VERSION 5.8 ;
BUSBITCHARS "[]" ;
DIVIDERCHAR "/" ;
UNITS
    DATABASE MICRONS 1000 ;
END UNITS

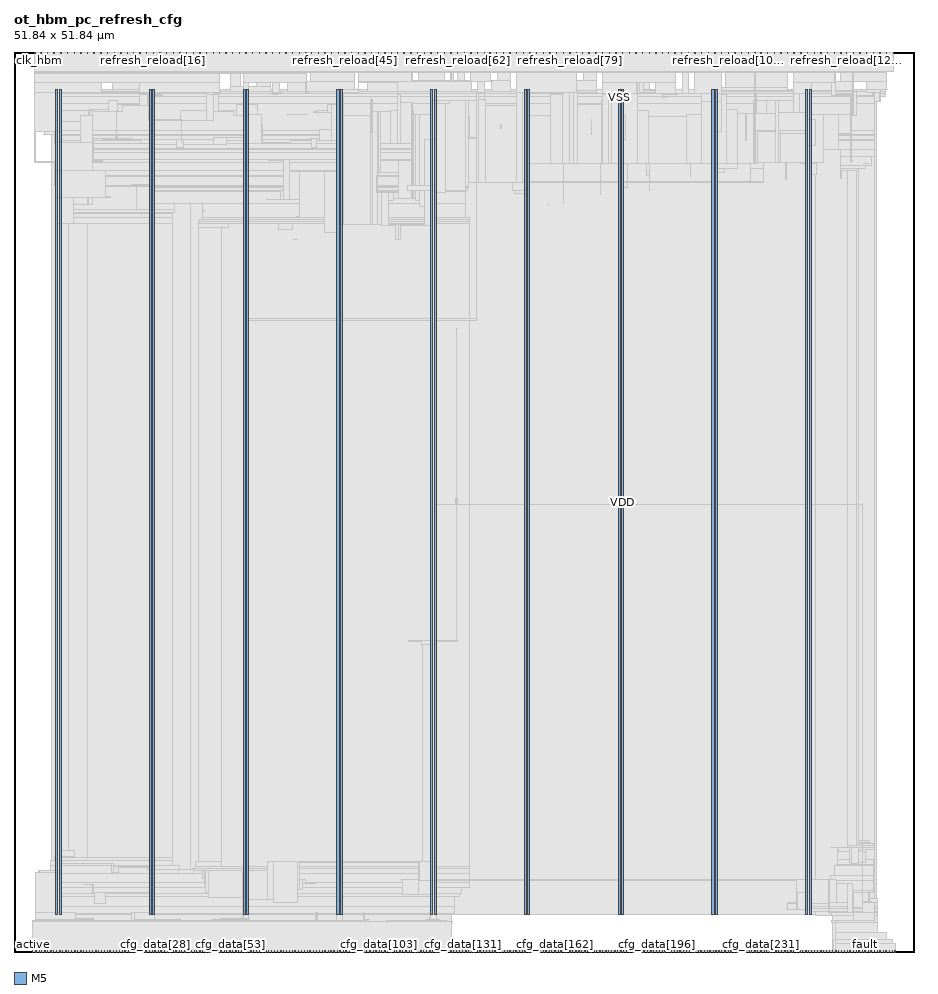
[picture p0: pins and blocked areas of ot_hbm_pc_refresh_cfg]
MACRO ot_hbm_pc_refresh_cfg
  FOREIGN ot_hbm_pc_refresh_cfg 0 0 ;
  CLASS BLOCK ;
  SIZE 51.84 BY 51.84 ;
  PIN active
    DIRECTION OUTPUT ;
    USE SIGNAL ;
    PORT
      LAYER M5 ;
        RECT  1.056 0 1.08 0.084 ;
    END
  END active
  PIN cfg_addr[0]
    DIRECTION INPUT ;
    USE SIGNAL ;
    PORT
      LAYER M5 ;
        RECT  1.248 0 1.272 0.084 ;
    END
  END cfg_addr[0]
  PIN cfg_addr[10]
    DIRECTION INPUT ;
    USE SIGNAL ;
    PORT
      LAYER M5 ;
        RECT  2.976 0 3 0.084 ;
    END
  END cfg_addr[10]
  PIN cfg_addr[11]
    DIRECTION INPUT ;
    USE SIGNAL ;
    PORT
      LAYER M5 ;
        RECT  3.12 0 3.144 0.084 ;
    END
  END cfg_addr[11]
  PIN cfg_addr[1]
    DIRECTION INPUT ;
    USE SIGNAL ;
    PORT
      LAYER M5 ;
        RECT  1.44 0 1.464 0.084 ;
    END
  END cfg_addr[1]
  PIN cfg_addr[2]
    DIRECTION INPUT ;
    USE SIGNAL ;
    PORT
      LAYER M5 ;
        RECT  1.584 0 1.608 0.084 ;
    END
  END cfg_addr[2]
  PIN cfg_addr[3]
    DIRECTION INPUT ;
    USE SIGNAL ;
    PORT
      LAYER M5 ;
        RECT  1.776 0 1.8 0.084 ;
    END
  END cfg_addr[3]
  PIN cfg_addr[4]
    DIRECTION INPUT ;
    USE SIGNAL ;
    PORT
      LAYER M5 ;
        RECT  1.92 0 1.944 0.084 ;
    END
  END cfg_addr[4]
  PIN cfg_addr[5]
    DIRECTION INPUT ;
    USE SIGNAL ;
    PORT
      LAYER M5 ;
        RECT  2.112 0 2.136 0.084 ;
    END
  END cfg_addr[5]
  PIN cfg_addr[6]
    DIRECTION INPUT ;
    USE SIGNAL ;
    PORT
      LAYER M5 ;
        RECT  2.256 0 2.28 0.084 ;
    END
  END cfg_addr[6]
  PIN cfg_addr[7]
    DIRECTION INPUT ;
    USE SIGNAL ;
    PORT
      LAYER M5 ;
        RECT  2.448 0 2.472 0.084 ;
    END
  END cfg_addr[7]
  PIN cfg_addr[8]
    DIRECTION INPUT ;
    USE SIGNAL ;
    PORT
      LAYER M5 ;
        RECT  2.64 0 2.664 0.084 ;
    END
  END cfg_addr[8]
  PIN cfg_addr[9]
    DIRECTION INPUT ;
    USE SIGNAL ;
    PORT
      LAYER M5 ;
        RECT  2.784 0 2.808 0.084 ;
    END
  END cfg_addr[9]
  PIN cfg_data[0]
    DIRECTION INPUT ;
    USE SIGNAL ;
    PORT
      LAYER M5 ;
        RECT  3.312 0 3.336 0.084 ;
    END
  END cfg_data[0]
  PIN cfg_data[100]
    DIRECTION INPUT ;
    USE SIGNAL ;
    PORT
      LAYER M5 ;
        RECT  20.496 0 20.52 0.084 ;
    END
  END cfg_data[100]
  PIN cfg_data[101]
    DIRECTION INPUT ;
    USE SIGNAL ;
    PORT
      LAYER M5 ;
        RECT  20.688 0 20.712 0.084 ;
    END
  END cfg_data[101]
  PIN cfg_data[102]
    DIRECTION INPUT ;
    USE SIGNAL ;
    PORT
      LAYER M5 ;
        RECT  20.832 0 20.856 0.084 ;
    END
  END cfg_data[102]
  PIN cfg_data[103]
    DIRECTION INPUT ;
    USE SIGNAL ;
    PORT
      LAYER M5 ;
        RECT  21.024 0 21.048 0.084 ;
    END
  END cfg_data[103]
  PIN cfg_data[104]
    DIRECTION INPUT ;
    USE SIGNAL ;
    PORT
      LAYER M5 ;
        RECT  21.168 0 21.192 0.084 ;
    END
  END cfg_data[104]
  PIN cfg_data[105]
    DIRECTION INPUT ;
    USE SIGNAL ;
    PORT
      LAYER M5 ;
        RECT  21.36 0 21.384 0.084 ;
    END
  END cfg_data[105]
  PIN cfg_data[106]
    DIRECTION INPUT ;
    USE SIGNAL ;
    PORT
      LAYER M5 ;
        RECT  21.504 0 21.528 0.084 ;
    END
  END cfg_data[106]
  PIN cfg_data[107]
    DIRECTION INPUT ;
    USE SIGNAL ;
    PORT
      LAYER M5 ;
        RECT  21.696 0 21.72 0.084 ;
    END
  END cfg_data[107]
  PIN cfg_data[108]
    DIRECTION INPUT ;
    USE SIGNAL ;
    PORT
      LAYER M5 ;
        RECT  21.888 0 21.912 0.084 ;
    END
  END cfg_data[108]
  PIN cfg_data[109]
    DIRECTION INPUT ;
    USE SIGNAL ;
    PORT
      LAYER M5 ;
        RECT  22.032 0 22.056 0.084 ;
    END
  END cfg_data[109]
  PIN cfg_data[10]
    DIRECTION INPUT ;
    USE SIGNAL ;
    PORT
      LAYER M5 ;
        RECT  5.04 0 5.064 0.084 ;
    END
  END cfg_data[10]
  PIN cfg_data[110]
    DIRECTION INPUT ;
    USE SIGNAL ;
    PORT
      LAYER M5 ;
        RECT  22.224 0 22.248 0.084 ;
    END
  END cfg_data[110]
  PIN cfg_data[111]
    DIRECTION INPUT ;
    USE SIGNAL ;
    PORT
      LAYER M5 ;
        RECT  22.368 0 22.392 0.084 ;
    END
  END cfg_data[111]
  PIN cfg_data[112]
    DIRECTION INPUT ;
    USE SIGNAL ;
    PORT
      LAYER M5 ;
        RECT  22.56 0 22.584 0.084 ;
    END
  END cfg_data[112]
  PIN cfg_data[113]
    DIRECTION INPUT ;
    USE SIGNAL ;
    PORT
      LAYER M5 ;
        RECT  22.752 0 22.776 0.084 ;
    END
  END cfg_data[113]
  PIN cfg_data[114]
    DIRECTION INPUT ;
    USE SIGNAL ;
    PORT
      LAYER M5 ;
        RECT  22.896 0 22.92 0.084 ;
    END
  END cfg_data[114]
  PIN cfg_data[115]
    DIRECTION INPUT ;
    USE SIGNAL ;
    PORT
      LAYER M5 ;
        RECT  23.088 0 23.112 0.084 ;
    END
  END cfg_data[115]
  PIN cfg_data[116]
    DIRECTION INPUT ;
    USE SIGNAL ;
    PORT
      LAYER M5 ;
        RECT  23.232 0 23.256 0.084 ;
    END
  END cfg_data[116]
  PIN cfg_data[117]
    DIRECTION INPUT ;
    USE SIGNAL ;
    PORT
      LAYER M5 ;
        RECT  23.424 0 23.448 0.084 ;
    END
  END cfg_data[117]
  PIN cfg_data[118]
    DIRECTION INPUT ;
    USE SIGNAL ;
    PORT
      LAYER M5 ;
        RECT  23.568 0 23.592 0.084 ;
    END
  END cfg_data[118]
  PIN cfg_data[119]
    DIRECTION INPUT ;
    USE SIGNAL ;
    PORT
      LAYER M5 ;
        RECT  23.76 0 23.784 0.084 ;
    END
  END cfg_data[119]
  PIN cfg_data[11]
    DIRECTION INPUT ;
    USE SIGNAL ;
    PORT
      LAYER M5 ;
        RECT  5.184 0 5.208 0.084 ;
    END
  END cfg_data[11]
  PIN cfg_data[120]
    DIRECTION INPUT ;
    USE SIGNAL ;
    PORT
      LAYER M5 ;
        RECT  23.952 0 23.976 0.084 ;
    END
  END cfg_data[120]
  PIN cfg_data[121]
    DIRECTION INPUT ;
    USE SIGNAL ;
    PORT
      LAYER M5 ;
        RECT  24.096 0 24.12 0.084 ;
    END
  END cfg_data[121]
  PIN cfg_data[122]
    DIRECTION INPUT ;
    USE SIGNAL ;
    PORT
      LAYER M5 ;
        RECT  24.288 0 24.312 0.084 ;
    END
  END cfg_data[122]
  PIN cfg_data[123]
    DIRECTION INPUT ;
    USE SIGNAL ;
    PORT
      LAYER M5 ;
        RECT  24.432 0 24.456 0.084 ;
    END
  END cfg_data[123]
  PIN cfg_data[124]
    DIRECTION INPUT ;
    USE SIGNAL ;
    PORT
      LAYER M5 ;
        RECT  24.624 0 24.648 0.084 ;
    END
  END cfg_data[124]
  PIN cfg_data[125]
    DIRECTION INPUT ;
    USE SIGNAL ;
    PORT
      LAYER M5 ;
        RECT  24.768 0 24.792 0.084 ;
    END
  END cfg_data[125]
  PIN cfg_data[126]
    DIRECTION INPUT ;
    USE SIGNAL ;
    PORT
      LAYER M5 ;
        RECT  24.96 0 24.984 0.084 ;
    END
  END cfg_data[126]
  PIN cfg_data[127]
    DIRECTION INPUT ;
    USE SIGNAL ;
    PORT
      LAYER M5 ;
        RECT  25.152 0 25.176 0.084 ;
    END
  END cfg_data[127]
  PIN cfg_data[128]
    DIRECTION INPUT ;
    USE SIGNAL ;
    PORT
      LAYER M5 ;
        RECT  25.296 0 25.32 0.084 ;
    END
  END cfg_data[128]
  PIN cfg_data[129]
    DIRECTION INPUT ;
    USE SIGNAL ;
    PORT
      LAYER M5 ;
        RECT  25.488 0 25.512 0.084 ;
    END
  END cfg_data[129]
  PIN cfg_data[12]
    DIRECTION INPUT ;
    USE SIGNAL ;
    PORT
      LAYER M5 ;
        RECT  5.376 0 5.4 0.084 ;
    END
  END cfg_data[12]
  PIN cfg_data[130]
    DIRECTION INPUT ;
    USE SIGNAL ;
    PORT
      LAYER M5 ;
        RECT  25.632 0 25.656 0.084 ;
    END
  END cfg_data[130]
  PIN cfg_data[131]
    DIRECTION INPUT ;
    USE SIGNAL ;
    PORT
      LAYER M5 ;
        RECT  25.824 0 25.848 0.084 ;
    END
  END cfg_data[131]
  PIN cfg_data[132]
    DIRECTION INPUT ;
    USE SIGNAL ;
    PORT
      LAYER M5 ;
        RECT  26.016 0 26.04 0.084 ;
    END
  END cfg_data[132]
  PIN cfg_data[133]
    DIRECTION INPUT ;
    USE SIGNAL ;
    PORT
      LAYER M5 ;
        RECT  26.16 0 26.184 0.084 ;
    END
  END cfg_data[133]
  PIN cfg_data[134]
    DIRECTION INPUT ;
    USE SIGNAL ;
    PORT
      LAYER M5 ;
        RECT  26.352 0 26.376 0.084 ;
    END
  END cfg_data[134]
  PIN cfg_data[135]
    DIRECTION INPUT ;
    USE SIGNAL ;
    PORT
      LAYER M5 ;
        RECT  26.496 0 26.52 0.084 ;
    END
  END cfg_data[135]
  PIN cfg_data[136]
    DIRECTION INPUT ;
    USE SIGNAL ;
    PORT
      LAYER M5 ;
        RECT  26.688 0 26.712 0.084 ;
    END
  END cfg_data[136]
  PIN cfg_data[137]
    DIRECTION INPUT ;
    USE SIGNAL ;
    PORT
      LAYER M5 ;
        RECT  26.832 0 26.856 0.084 ;
    END
  END cfg_data[137]
  PIN cfg_data[138]
    DIRECTION INPUT ;
    USE SIGNAL ;
    PORT
      LAYER M5 ;
        RECT  27.024 0 27.048 0.084 ;
    END
  END cfg_data[138]
  PIN cfg_data[139]
    DIRECTION INPUT ;
    USE SIGNAL ;
    PORT
      LAYER M5 ;
        RECT  27.216 0 27.24 0.084 ;
    END
  END cfg_data[139]
  PIN cfg_data[13]
    DIRECTION INPUT ;
    USE SIGNAL ;
    PORT
      LAYER M5 ;
        RECT  5.52 0 5.544 0.084 ;
    END
  END cfg_data[13]
  PIN cfg_data[140]
    DIRECTION INPUT ;
    USE SIGNAL ;
    PORT
      LAYER M5 ;
        RECT  27.36 0 27.384 0.084 ;
    END
  END cfg_data[140]
  PIN cfg_data[141]
    DIRECTION INPUT ;
    USE SIGNAL ;
    PORT
      LAYER M5 ;
        RECT  27.552 0 27.576 0.084 ;
    END
  END cfg_data[141]
  PIN cfg_data[142]
    DIRECTION INPUT ;
    USE SIGNAL ;
    PORT
      LAYER M5 ;
        RECT  27.696 0 27.72 0.084 ;
    END
  END cfg_data[142]
  PIN cfg_data[143]
    DIRECTION INPUT ;
    USE SIGNAL ;
    PORT
      LAYER M5 ;
        RECT  27.888 0 27.912 0.084 ;
    END
  END cfg_data[143]
  PIN cfg_data[144]
    DIRECTION INPUT ;
    USE SIGNAL ;
    PORT
      LAYER M5 ;
        RECT  28.08 0 28.104 0.084 ;
    END
  END cfg_data[144]
  PIN cfg_data[145]
    DIRECTION INPUT ;
    USE SIGNAL ;
    PORT
      LAYER M5 ;
        RECT  28.224 0 28.248 0.084 ;
    END
  END cfg_data[145]
  PIN cfg_data[146]
    DIRECTION INPUT ;
    USE SIGNAL ;
    PORT
      LAYER M5 ;
        RECT  28.416 0 28.44 0.084 ;
    END
  END cfg_data[146]
  PIN cfg_data[147]
    DIRECTION INPUT ;
    USE SIGNAL ;
    PORT
      LAYER M5 ;
        RECT  28.56 0 28.584 0.084 ;
    END
  END cfg_data[147]
  PIN cfg_data[148]
    DIRECTION INPUT ;
    USE SIGNAL ;
    PORT
      LAYER M5 ;
        RECT  28.752 0 28.776 0.084 ;
    END
  END cfg_data[148]
  PIN cfg_data[149]
    DIRECTION INPUT ;
    USE SIGNAL ;
    PORT
      LAYER M5 ;
        RECT  28.896 0 28.92 0.084 ;
    END
  END cfg_data[149]
  PIN cfg_data[14]
    DIRECTION INPUT ;
    USE SIGNAL ;
    PORT
      LAYER M5 ;
        RECT  5.712 0 5.736 0.084 ;
    END
  END cfg_data[14]
  PIN cfg_data[150]
    DIRECTION INPUT ;
    USE SIGNAL ;
    PORT
      LAYER M5 ;
        RECT  29.088 0 29.112 0.084 ;
    END
  END cfg_data[150]
  PIN cfg_data[151]
    DIRECTION INPUT ;
    USE SIGNAL ;
    PORT
      LAYER M5 ;
        RECT  29.28 0 29.304 0.084 ;
    END
  END cfg_data[151]
  PIN cfg_data[152]
    DIRECTION INPUT ;
    USE SIGNAL ;
    PORT
      LAYER M5 ;
        RECT  29.424 0 29.448 0.084 ;
    END
  END cfg_data[152]
  PIN cfg_data[153]
    DIRECTION INPUT ;
    USE SIGNAL ;
    PORT
      LAYER M5 ;
        RECT  29.616 0 29.64 0.084 ;
    END
  END cfg_data[153]
  PIN cfg_data[154]
    DIRECTION INPUT ;
    USE SIGNAL ;
    PORT
      LAYER M5 ;
        RECT  29.76 0 29.784 0.084 ;
    END
  END cfg_data[154]
  PIN cfg_data[155]
    DIRECTION INPUT ;
    USE SIGNAL ;
    PORT
      LAYER M5 ;
        RECT  29.952 0 29.976 0.084 ;
    END
  END cfg_data[155]
  PIN cfg_data[156]
    DIRECTION INPUT ;
    USE SIGNAL ;
    PORT
      LAYER M5 ;
        RECT  30.096 0 30.12 0.084 ;
    END
  END cfg_data[156]
  PIN cfg_data[157]
    DIRECTION INPUT ;
    USE SIGNAL ;
    PORT
      LAYER M5 ;
        RECT  30.288 0 30.312 0.084 ;
    END
  END cfg_data[157]
  PIN cfg_data[158]
    DIRECTION INPUT ;
    USE SIGNAL ;
    PORT
      LAYER M5 ;
        RECT  30.48 0 30.504 0.084 ;
    END
  END cfg_data[158]
  PIN cfg_data[159]
    DIRECTION INPUT ;
    USE SIGNAL ;
    PORT
      LAYER M5 ;
        RECT  30.624 0 30.648 0.084 ;
    END
  END cfg_data[159]
  PIN cfg_data[15]
    DIRECTION INPUT ;
    USE SIGNAL ;
    PORT
      LAYER M5 ;
        RECT  5.904 0 5.928 0.084 ;
    END
  END cfg_data[15]
  PIN cfg_data[160]
    DIRECTION INPUT ;
    USE SIGNAL ;
    PORT
      LAYER M5 ;
        RECT  30.816 0 30.84 0.084 ;
    END
  END cfg_data[160]
  PIN cfg_data[161]
    DIRECTION INPUT ;
    USE SIGNAL ;
    PORT
      LAYER M5 ;
        RECT  30.96 0 30.984 0.084 ;
    END
  END cfg_data[161]
  PIN cfg_data[162]
    DIRECTION INPUT ;
    USE SIGNAL ;
    PORT
      LAYER M5 ;
        RECT  31.152 0 31.176 0.084 ;
    END
  END cfg_data[162]
  PIN cfg_data[163]
    DIRECTION INPUT ;
    USE SIGNAL ;
    PORT
      LAYER M5 ;
        RECT  31.344 0 31.368 0.084 ;
    END
  END cfg_data[163]
  PIN cfg_data[164]
    DIRECTION INPUT ;
    USE SIGNAL ;
    PORT
      LAYER M5 ;
        RECT  31.488 0 31.512 0.084 ;
    END
  END cfg_data[164]
  PIN cfg_data[165]
    DIRECTION INPUT ;
    USE SIGNAL ;
    PORT
      LAYER M5 ;
        RECT  31.68 0 31.704 0.084 ;
    END
  END cfg_data[165]
  PIN cfg_data[166]
    DIRECTION INPUT ;
    USE SIGNAL ;
    PORT
      LAYER M5 ;
        RECT  31.824 0 31.848 0.084 ;
    END
  END cfg_data[166]
  PIN cfg_data[167]
    DIRECTION INPUT ;
    USE SIGNAL ;
    PORT
      LAYER M5 ;
        RECT  32.016 0 32.04 0.084 ;
    END
  END cfg_data[167]
  PIN cfg_data[168]
    DIRECTION INPUT ;
    USE SIGNAL ;
    PORT
      LAYER M5 ;
        RECT  32.16 0 32.184 0.084 ;
    END
  END cfg_data[168]
  PIN cfg_data[169]
    DIRECTION INPUT ;
    USE SIGNAL ;
    PORT
      LAYER M5 ;
        RECT  32.352 0 32.376 0.084 ;
    END
  END cfg_data[169]
  PIN cfg_data[16]
    DIRECTION INPUT ;
    USE SIGNAL ;
    PORT
      LAYER M5 ;
        RECT  6.048 0 6.072 0.084 ;
    END
  END cfg_data[16]
  PIN cfg_data[170]
    DIRECTION INPUT ;
    USE SIGNAL ;
    PORT
      LAYER M5 ;
        RECT  32.544 0 32.568 0.084 ;
    END
  END cfg_data[170]
  PIN cfg_data[171]
    DIRECTION INPUT ;
    USE SIGNAL ;
    PORT
      LAYER M5 ;
        RECT  32.688 0 32.712 0.084 ;
    END
  END cfg_data[171]
  PIN cfg_data[172]
    DIRECTION INPUT ;
    USE SIGNAL ;
    PORT
      LAYER M5 ;
        RECT  32.88 0 32.904 0.084 ;
    END
  END cfg_data[172]
  PIN cfg_data[173]
    DIRECTION INPUT ;
    USE SIGNAL ;
    PORT
      LAYER M5 ;
        RECT  33.024 0 33.048 0.084 ;
    END
  END cfg_data[173]
  PIN cfg_data[174]
    DIRECTION INPUT ;
    USE SIGNAL ;
    PORT
      LAYER M5 ;
        RECT  33.216 0 33.24 0.084 ;
    END
  END cfg_data[174]
  PIN cfg_data[175]
    DIRECTION INPUT ;
    USE SIGNAL ;
    PORT
      LAYER M5 ;
        RECT  33.408 0 33.432 0.084 ;
    END
  END cfg_data[175]
  PIN cfg_data[176]
    DIRECTION INPUT ;
    USE SIGNAL ;
    PORT
      LAYER M5 ;
        RECT  33.552 0 33.576 0.084 ;
    END
  END cfg_data[176]
  PIN cfg_data[177]
    DIRECTION INPUT ;
    USE SIGNAL ;
    PORT
      LAYER M5 ;
        RECT  33.744 0 33.768 0.084 ;
    END
  END cfg_data[177]
  PIN cfg_data[178]
    DIRECTION INPUT ;
    USE SIGNAL ;
    PORT
      LAYER M5 ;
        RECT  33.888 0 33.912 0.084 ;
    END
  END cfg_data[178]
  PIN cfg_data[179]
    DIRECTION INPUT ;
    USE SIGNAL ;
    PORT
      LAYER M5 ;
        RECT  34.08 0 34.104 0.084 ;
    END
  END cfg_data[179]
  PIN cfg_data[17]
    DIRECTION INPUT ;
    USE SIGNAL ;
    PORT
      LAYER M5 ;
        RECT  6.24 0 6.264 0.084 ;
    END
  END cfg_data[17]
  PIN cfg_data[180]
    DIRECTION INPUT ;
    USE SIGNAL ;
    PORT
      LAYER M5 ;
        RECT  34.224 0 34.248 0.084 ;
    END
  END cfg_data[180]
  PIN cfg_data[181]
    DIRECTION INPUT ;
    USE SIGNAL ;
    PORT
      LAYER M5 ;
        RECT  34.416 0 34.44 0.084 ;
    END
  END cfg_data[181]
  PIN cfg_data[182]
    DIRECTION INPUT ;
    USE SIGNAL ;
    PORT
      LAYER M5 ;
        RECT  34.608 0 34.632 0.084 ;
    END
  END cfg_data[182]
  PIN cfg_data[183]
    DIRECTION INPUT ;
    USE SIGNAL ;
    PORT
      LAYER M5 ;
        RECT  34.752 0 34.776 0.084 ;
    END
  END cfg_data[183]
  PIN cfg_data[184]
    DIRECTION INPUT ;
    USE SIGNAL ;
    PORT
      LAYER M5 ;
        RECT  34.944 0 34.968 0.084 ;
    END
  END cfg_data[184]
  PIN cfg_data[185]
    DIRECTION INPUT ;
    USE SIGNAL ;
    PORT
      LAYER M5 ;
        RECT  35.088 0 35.112 0.084 ;
    END
  END cfg_data[185]
  PIN cfg_data[186]
    DIRECTION INPUT ;
    USE SIGNAL ;
    PORT
      LAYER M5 ;
        RECT  35.28 0 35.304 0.084 ;
    END
  END cfg_data[186]
  PIN cfg_data[187]
    DIRECTION INPUT ;
    USE SIGNAL ;
    PORT
      LAYER M5 ;
        RECT  35.424 0 35.448 0.084 ;
    END
  END cfg_data[187]
  PIN cfg_data[188]
    DIRECTION INPUT ;
    USE SIGNAL ;
    PORT
      LAYER M5 ;
        RECT  35.616 0 35.64 0.084 ;
    END
  END cfg_data[188]
  PIN cfg_data[189]
    DIRECTION INPUT ;
    USE SIGNAL ;
    PORT
      LAYER M5 ;
        RECT  35.808 0 35.832 0.084 ;
    END
  END cfg_data[189]
  PIN cfg_data[18]
    DIRECTION INPUT ;
    USE SIGNAL ;
    PORT
      LAYER M5 ;
        RECT  6.384 0 6.408 0.084 ;
    END
  END cfg_data[18]
  PIN cfg_data[190]
    DIRECTION INPUT ;
    USE SIGNAL ;
    PORT
      LAYER M5 ;
        RECT  35.952 0 35.976 0.084 ;
    END
  END cfg_data[190]
  PIN cfg_data[191]
    DIRECTION INPUT ;
    USE SIGNAL ;
    PORT
      LAYER M5 ;
        RECT  36.144 0 36.168 0.084 ;
    END
  END cfg_data[191]
  PIN cfg_data[192]
    DIRECTION INPUT ;
    USE SIGNAL ;
    PORT
      LAYER M5 ;
        RECT  36.288 0 36.312 0.084 ;
    END
  END cfg_data[192]
  PIN cfg_data[193]
    DIRECTION INPUT ;
    USE SIGNAL ;
    PORT
      LAYER M5 ;
        RECT  36.48 0 36.504 0.084 ;
    END
  END cfg_data[193]
  PIN cfg_data[194]
    DIRECTION INPUT ;
    USE SIGNAL ;
    PORT
      LAYER M5 ;
        RECT  36.672 0 36.696 0.084 ;
    END
  END cfg_data[194]
  PIN cfg_data[195]
    DIRECTION INPUT ;
    USE SIGNAL ;
    PORT
      LAYER M5 ;
        RECT  36.816 0 36.84 0.084 ;
    END
  END cfg_data[195]
  PIN cfg_data[196]
    DIRECTION INPUT ;
    USE SIGNAL ;
    PORT
      LAYER M5 ;
        RECT  37.008 0 37.032 0.084 ;
    END
  END cfg_data[196]
  PIN cfg_data[197]
    DIRECTION INPUT ;
    USE SIGNAL ;
    PORT
      LAYER M5 ;
        RECT  37.152 0 37.176 0.084 ;
    END
  END cfg_data[197]
  PIN cfg_data[198]
    DIRECTION INPUT ;
    USE SIGNAL ;
    PORT
      LAYER M5 ;
        RECT  37.344 0 37.368 0.084 ;
    END
  END cfg_data[198]
  PIN cfg_data[199]
    DIRECTION INPUT ;
    USE SIGNAL ;
    PORT
      LAYER M5 ;
        RECT  37.488 0 37.512 0.084 ;
    END
  END cfg_data[199]
  PIN cfg_data[19]
    DIRECTION INPUT ;
    USE SIGNAL ;
    PORT
      LAYER M5 ;
        RECT  6.576 0 6.6 0.084 ;
    END
  END cfg_data[19]
  PIN cfg_data[1]
    DIRECTION INPUT ;
    USE SIGNAL ;
    PORT
      LAYER M5 ;
        RECT  3.504 0 3.528 0.084 ;
    END
  END cfg_data[1]
  PIN cfg_data[200]
    DIRECTION INPUT ;
    USE SIGNAL ;
    PORT
      LAYER M5 ;
        RECT  37.68 0 37.704 0.084 ;
    END
  END cfg_data[200]
  PIN cfg_data[201]
    DIRECTION INPUT ;
    USE SIGNAL ;
    PORT
      LAYER M5 ;
        RECT  37.872 0 37.896 0.084 ;
    END
  END cfg_data[201]
  PIN cfg_data[202]
    DIRECTION INPUT ;
    USE SIGNAL ;
    PORT
      LAYER M5 ;
        RECT  38.016 0 38.04 0.084 ;
    END
  END cfg_data[202]
  PIN cfg_data[203]
    DIRECTION INPUT ;
    USE SIGNAL ;
    PORT
      LAYER M5 ;
        RECT  38.208 0 38.232 0.084 ;
    END
  END cfg_data[203]
  PIN cfg_data[204]
    DIRECTION INPUT ;
    USE SIGNAL ;
    PORT
      LAYER M5 ;
        RECT  38.352 0 38.376 0.084 ;
    END
  END cfg_data[204]
  PIN cfg_data[205]
    DIRECTION INPUT ;
    USE SIGNAL ;
    PORT
      LAYER M5 ;
        RECT  38.544 0 38.568 0.084 ;
    END
  END cfg_data[205]
  PIN cfg_data[206]
    DIRECTION INPUT ;
    USE SIGNAL ;
    PORT
      LAYER M5 ;
        RECT  38.736 0 38.76 0.084 ;
    END
  END cfg_data[206]
  PIN cfg_data[207]
    DIRECTION INPUT ;
    USE SIGNAL ;
    PORT
      LAYER M5 ;
        RECT  38.88 0 38.904 0.084 ;
    END
  END cfg_data[207]
  PIN cfg_data[208]
    DIRECTION INPUT ;
    USE SIGNAL ;
    PORT
      LAYER M5 ;
        RECT  39.072 0 39.096 0.084 ;
    END
  END cfg_data[208]
  PIN cfg_data[209]
    DIRECTION INPUT ;
    USE SIGNAL ;
    PORT
      LAYER M5 ;
        RECT  39.216 0 39.24 0.084 ;
    END
  END cfg_data[209]
  PIN cfg_data[20]
    DIRECTION INPUT ;
    USE SIGNAL ;
    PORT
      LAYER M5 ;
        RECT  6.768 0 6.792 0.084 ;
    END
  END cfg_data[20]
  PIN cfg_data[210]
    DIRECTION INPUT ;
    USE SIGNAL ;
    PORT
      LAYER M5 ;
        RECT  39.408 0 39.432 0.084 ;
    END
  END cfg_data[210]
  PIN cfg_data[211]
    DIRECTION INPUT ;
    USE SIGNAL ;
    PORT
      LAYER M5 ;
        RECT  39.552 0 39.576 0.084 ;
    END
  END cfg_data[211]
  PIN cfg_data[212]
    DIRECTION INPUT ;
    USE SIGNAL ;
    PORT
      LAYER M5 ;
        RECT  39.744 0 39.768 0.084 ;
    END
  END cfg_data[212]
  PIN cfg_data[213]
    DIRECTION INPUT ;
    USE SIGNAL ;
    PORT
      LAYER M5 ;
        RECT  39.936 0 39.96 0.084 ;
    END
  END cfg_data[213]
  PIN cfg_data[214]
    DIRECTION INPUT ;
    USE SIGNAL ;
    PORT
      LAYER M5 ;
        RECT  40.08 0 40.104 0.084 ;
    END
  END cfg_data[214]
  PIN cfg_data[215]
    DIRECTION INPUT ;
    USE SIGNAL ;
    PORT
      LAYER M5 ;
        RECT  40.272 0 40.296 0.084 ;
    END
  END cfg_data[215]
  PIN cfg_data[216]
    DIRECTION INPUT ;
    USE SIGNAL ;
    PORT
      LAYER M5 ;
        RECT  40.416 0 40.44 0.084 ;
    END
  END cfg_data[216]
  PIN cfg_data[217]
    DIRECTION INPUT ;
    USE SIGNAL ;
    PORT
      LAYER M5 ;
        RECT  40.608 0 40.632 0.084 ;
    END
  END cfg_data[217]
  PIN cfg_data[218]
    DIRECTION INPUT ;
    USE SIGNAL ;
    PORT
      LAYER M5 ;
        RECT  40.752 0 40.776 0.084 ;
    END
  END cfg_data[218]
  PIN cfg_data[219]
    DIRECTION INPUT ;
    USE SIGNAL ;
    PORT
      LAYER M5 ;
        RECT  40.944 0 40.968 0.084 ;
    END
  END cfg_data[219]
  PIN cfg_data[21]
    DIRECTION INPUT ;
    USE SIGNAL ;
    PORT
      LAYER M5 ;
        RECT  6.912 0 6.936 0.084 ;
    END
  END cfg_data[21]
  PIN cfg_data[220]
    DIRECTION INPUT ;
    USE SIGNAL ;
    PORT
      LAYER M5 ;
        RECT  41.136 0 41.16 0.084 ;
    END
  END cfg_data[220]
  PIN cfg_data[221]
    DIRECTION INPUT ;
    USE SIGNAL ;
    PORT
      LAYER M5 ;
        RECT  41.28 0 41.304 0.084 ;
    END
  END cfg_data[221]
  PIN cfg_data[222]
    DIRECTION INPUT ;
    USE SIGNAL ;
    PORT
      LAYER M5 ;
        RECT  41.472 0 41.496 0.084 ;
    END
  END cfg_data[222]
  PIN cfg_data[223]
    DIRECTION INPUT ;
    USE SIGNAL ;
    PORT
      LAYER M5 ;
        RECT  41.616 0 41.64 0.084 ;
    END
  END cfg_data[223]
  PIN cfg_data[224]
    DIRECTION INPUT ;
    USE SIGNAL ;
    PORT
      LAYER M5 ;
        RECT  41.808 0 41.832 0.084 ;
    END
  END cfg_data[224]
  PIN cfg_data[225]
    DIRECTION INPUT ;
    USE SIGNAL ;
    PORT
      LAYER M5 ;
        RECT  42 0 42.024 0.084 ;
    END
  END cfg_data[225]
  PIN cfg_data[226]
    DIRECTION INPUT ;
    USE SIGNAL ;
    PORT
      LAYER M5 ;
        RECT  42.144 0 42.168 0.084 ;
    END
  END cfg_data[226]
  PIN cfg_data[227]
    DIRECTION INPUT ;
    USE SIGNAL ;
    PORT
      LAYER M5 ;
        RECT  42.336 0 42.36 0.084 ;
    END
  END cfg_data[227]
  PIN cfg_data[228]
    DIRECTION INPUT ;
    USE SIGNAL ;
    PORT
      LAYER M5 ;
        RECT  42.48 0 42.504 0.084 ;
    END
  END cfg_data[228]
  PIN cfg_data[229]
    DIRECTION INPUT ;
    USE SIGNAL ;
    PORT
      LAYER M5 ;
        RECT  42.672 0 42.696 0.084 ;
    END
  END cfg_data[229]
  PIN cfg_data[22]
    DIRECTION INPUT ;
    USE SIGNAL ;
    PORT
      LAYER M5 ;
        RECT  7.104 0 7.128 0.084 ;
    END
  END cfg_data[22]
  PIN cfg_data[230]
    DIRECTION INPUT ;
    USE SIGNAL ;
    PORT
      LAYER M5 ;
        RECT  42.816 0 42.84 0.084 ;
    END
  END cfg_data[230]
  PIN cfg_data[231]
    DIRECTION INPUT ;
    USE SIGNAL ;
    PORT
      LAYER M5 ;
        RECT  43.008 0 43.032 0.084 ;
    END
  END cfg_data[231]
  PIN cfg_data[232]
    DIRECTION INPUT ;
    USE SIGNAL ;
    PORT
      LAYER M5 ;
        RECT  43.2 0 43.224 0.084 ;
    END
  END cfg_data[232]
  PIN cfg_data[233]
    DIRECTION INPUT ;
    USE SIGNAL ;
    PORT
      LAYER M5 ;
        RECT  43.344 0 43.368 0.084 ;
    END
  END cfg_data[233]
  PIN cfg_data[234]
    DIRECTION INPUT ;
    USE SIGNAL ;
    PORT
      LAYER M5 ;
        RECT  43.536 0 43.56 0.084 ;
    END
  END cfg_data[234]
  PIN cfg_data[235]
    DIRECTION INPUT ;
    USE SIGNAL ;
    PORT
      LAYER M5 ;
        RECT  43.68 0 43.704 0.084 ;
    END
  END cfg_data[235]
  PIN cfg_data[236]
    DIRECTION INPUT ;
    USE SIGNAL ;
    PORT
      LAYER M5 ;
        RECT  43.872 0 43.896 0.084 ;
    END
  END cfg_data[236]
  PIN cfg_data[237]
    DIRECTION INPUT ;
    USE SIGNAL ;
    PORT
      LAYER M5 ;
        RECT  44.016 0 44.04 0.084 ;
    END
  END cfg_data[237]
  PIN cfg_data[238]
    DIRECTION INPUT ;
    USE SIGNAL ;
    PORT
      LAYER M5 ;
        RECT  44.208 0 44.232 0.084 ;
    END
  END cfg_data[238]
  PIN cfg_data[239]
    DIRECTION INPUT ;
    USE SIGNAL ;
    PORT
      LAYER M5 ;
        RECT  44.4 0 44.424 0.084 ;
    END
  END cfg_data[239]
  PIN cfg_data[23]
    DIRECTION INPUT ;
    USE SIGNAL ;
    PORT
      LAYER M5 ;
        RECT  7.248 0 7.272 0.084 ;
    END
  END cfg_data[23]
  PIN cfg_data[240]
    DIRECTION INPUT ;
    USE SIGNAL ;
    PORT
      LAYER M5 ;
        RECT  44.544 0 44.568 0.084 ;
    END
  END cfg_data[240]
  PIN cfg_data[241]
    DIRECTION INPUT ;
    USE SIGNAL ;
    PORT
      LAYER M5 ;
        RECT  44.736 0 44.76 0.084 ;
    END
  END cfg_data[241]
  PIN cfg_data[242]
    DIRECTION INPUT ;
    USE SIGNAL ;
    PORT
      LAYER M5 ;
        RECT  44.88 0 44.904 0.084 ;
    END
  END cfg_data[242]
  PIN cfg_data[243]
    DIRECTION INPUT ;
    USE SIGNAL ;
    PORT
      LAYER M5 ;
        RECT  45.072 0 45.096 0.084 ;
    END
  END cfg_data[243]
  PIN cfg_data[244]
    DIRECTION INPUT ;
    USE SIGNAL ;
    PORT
      LAYER M5 ;
        RECT  45.264 0 45.288 0.084 ;
    END
  END cfg_data[244]
  PIN cfg_data[245]
    DIRECTION INPUT ;
    USE SIGNAL ;
    PORT
      LAYER M5 ;
        RECT  45.408 0 45.432 0.084 ;
    END
  END cfg_data[245]
  PIN cfg_data[246]
    DIRECTION INPUT ;
    USE SIGNAL ;
    PORT
      LAYER M5 ;
        RECT  45.6 0 45.624 0.084 ;
    END
  END cfg_data[246]
  PIN cfg_data[247]
    DIRECTION INPUT ;
    USE SIGNAL ;
    PORT
      LAYER M5 ;
        RECT  45.744 0 45.768 0.084 ;
    END
  END cfg_data[247]
  PIN cfg_data[248]
    DIRECTION INPUT ;
    USE SIGNAL ;
    PORT
      LAYER M5 ;
        RECT  45.936 0 45.96 0.084 ;
    END
  END cfg_data[248]
  PIN cfg_data[249]
    DIRECTION INPUT ;
    USE SIGNAL ;
    PORT
      LAYER M5 ;
        RECT  46.08 0 46.104 0.084 ;
    END
  END cfg_data[249]
  PIN cfg_data[24]
    DIRECTION INPUT ;
    USE SIGNAL ;
    PORT
      LAYER M5 ;
        RECT  7.44 0 7.464 0.084 ;
    END
  END cfg_data[24]
  PIN cfg_data[250]
    DIRECTION INPUT ;
    USE SIGNAL ;
    PORT
      LAYER M5 ;
        RECT  46.272 0 46.296 0.084 ;
    END
  END cfg_data[250]
  PIN cfg_data[251]
    DIRECTION INPUT ;
    USE SIGNAL ;
    PORT
      LAYER M5 ;
        RECT  46.464 0 46.488 0.084 ;
    END
  END cfg_data[251]
  PIN cfg_data[252]
    DIRECTION INPUT ;
    USE SIGNAL ;
    PORT
      LAYER M5 ;
        RECT  46.608 0 46.632 0.084 ;
    END
  END cfg_data[252]
  PIN cfg_data[253]
    DIRECTION INPUT ;
    USE SIGNAL ;
    PORT
      LAYER M5 ;
        RECT  46.8 0 46.824 0.084 ;
    END
  END cfg_data[253]
  PIN cfg_data[254]
    DIRECTION INPUT ;
    USE SIGNAL ;
    PORT
      LAYER M5 ;
        RECT  46.944 0 46.968 0.084 ;
    END
  END cfg_data[254]
  PIN cfg_data[255]
    DIRECTION INPUT ;
    USE SIGNAL ;
    PORT
      LAYER M5 ;
        RECT  47.136 0 47.16 0.084 ;
    END
  END cfg_data[255]
  PIN cfg_data[25]
    DIRECTION INPUT ;
    USE SIGNAL ;
    PORT
      LAYER M5 ;
        RECT  7.584 0 7.608 0.084 ;
    END
  END cfg_data[25]
  PIN cfg_data[26]
    DIRECTION INPUT ;
    USE SIGNAL ;
    PORT
      LAYER M5 ;
        RECT  7.776 0 7.8 0.084 ;
    END
  END cfg_data[26]
  PIN cfg_data[27]
    DIRECTION INPUT ;
    USE SIGNAL ;
    PORT
      LAYER M5 ;
        RECT  7.968 0 7.992 0.084 ;
    END
  END cfg_data[27]
  PIN cfg_data[28]
    DIRECTION INPUT ;
    USE SIGNAL ;
    PORT
      LAYER M5 ;
        RECT  8.112 0 8.136 0.084 ;
    END
  END cfg_data[28]
  PIN cfg_data[29]
    DIRECTION INPUT ;
    USE SIGNAL ;
    PORT
      LAYER M5 ;
        RECT  8.304 0 8.328 0.084 ;
    END
  END cfg_data[29]
  PIN cfg_data[2]
    DIRECTION INPUT ;
    USE SIGNAL ;
    PORT
      LAYER M5 ;
        RECT  3.648 0 3.672 0.084 ;
    END
  END cfg_data[2]
  PIN cfg_data[30]
    DIRECTION INPUT ;
    USE SIGNAL ;
    PORT
      LAYER M5 ;
        RECT  8.448 0 8.472 0.084 ;
    END
  END cfg_data[30]
  PIN cfg_data[31]
    DIRECTION INPUT ;
    USE SIGNAL ;
    PORT
      LAYER M5 ;
        RECT  8.64 0 8.664 0.084 ;
    END
  END cfg_data[31]
  PIN cfg_data[32]
    DIRECTION INPUT ;
    USE SIGNAL ;
    PORT
      LAYER M5 ;
        RECT  8.832 0 8.856 0.084 ;
    END
  END cfg_data[32]
  PIN cfg_data[33]
    DIRECTION INPUT ;
    USE SIGNAL ;
    PORT
      LAYER M5 ;
        RECT  8.976 0 9 0.084 ;
    END
  END cfg_data[33]
  PIN cfg_data[34]
    DIRECTION INPUT ;
    USE SIGNAL ;
    PORT
      LAYER M5 ;
        RECT  9.168 0 9.192 0.084 ;
    END
  END cfg_data[34]
  PIN cfg_data[35]
    DIRECTION INPUT ;
    USE SIGNAL ;
    PORT
      LAYER M5 ;
        RECT  9.312 0 9.336 0.084 ;
    END
  END cfg_data[35]
  PIN cfg_data[36]
    DIRECTION INPUT ;
    USE SIGNAL ;
    PORT
      LAYER M5 ;
        RECT  9.504 0 9.528 0.084 ;
    END
  END cfg_data[36]
  PIN cfg_data[37]
    DIRECTION INPUT ;
    USE SIGNAL ;
    PORT
      LAYER M5 ;
        RECT  9.648 0 9.672 0.084 ;
    END
  END cfg_data[37]
  PIN cfg_data[38]
    DIRECTION INPUT ;
    USE SIGNAL ;
    PORT
      LAYER M5 ;
        RECT  9.84 0 9.864 0.084 ;
    END
  END cfg_data[38]
  PIN cfg_data[39]
    DIRECTION INPUT ;
    USE SIGNAL ;
    PORT
      LAYER M5 ;
        RECT  10.032 0 10.056 0.084 ;
    END
  END cfg_data[39]
  PIN cfg_data[3]
    DIRECTION INPUT ;
    USE SIGNAL ;
    PORT
      LAYER M5 ;
        RECT  3.84 0 3.864 0.084 ;
    END
  END cfg_data[3]
  PIN cfg_data[40]
    DIRECTION INPUT ;
    USE SIGNAL ;
    PORT
      LAYER M5 ;
        RECT  10.176 0 10.2 0.084 ;
    END
  END cfg_data[40]
  PIN cfg_data[41]
    DIRECTION INPUT ;
    USE SIGNAL ;
    PORT
      LAYER M5 ;
        RECT  10.368 0 10.392 0.084 ;
    END
  END cfg_data[41]
  PIN cfg_data[42]
    DIRECTION INPUT ;
    USE SIGNAL ;
    PORT
      LAYER M5 ;
        RECT  10.512 0 10.536 0.084 ;
    END
  END cfg_data[42]
  PIN cfg_data[43]
    DIRECTION INPUT ;
    USE SIGNAL ;
    PORT
      LAYER M5 ;
        RECT  10.704 0 10.728 0.084 ;
    END
  END cfg_data[43]
  PIN cfg_data[44]
    DIRECTION INPUT ;
    USE SIGNAL ;
    PORT
      LAYER M5 ;
        RECT  10.848 0 10.872 0.084 ;
    END
  END cfg_data[44]
  PIN cfg_data[45]
    DIRECTION INPUT ;
    USE SIGNAL ;
    PORT
      LAYER M5 ;
        RECT  11.04 0 11.064 0.084 ;
    END
  END cfg_data[45]
  PIN cfg_data[46]
    DIRECTION INPUT ;
    USE SIGNAL ;
    PORT
      LAYER M5 ;
        RECT  11.232 0 11.256 0.084 ;
    END
  END cfg_data[46]
  PIN cfg_data[47]
    DIRECTION INPUT ;
    USE SIGNAL ;
    PORT
      LAYER M5 ;
        RECT  11.376 0 11.4 0.084 ;
    END
  END cfg_data[47]
  PIN cfg_data[48]
    DIRECTION INPUT ;
    USE SIGNAL ;
    PORT
      LAYER M5 ;
        RECT  11.568 0 11.592 0.084 ;
    END
  END cfg_data[48]
  PIN cfg_data[49]
    DIRECTION INPUT ;
    USE SIGNAL ;
    PORT
      LAYER M5 ;
        RECT  11.712 0 11.736 0.084 ;
    END
  END cfg_data[49]
  PIN cfg_data[4]
    DIRECTION INPUT ;
    USE SIGNAL ;
    PORT
      LAYER M5 ;
        RECT  3.984 0 4.008 0.084 ;
    END
  END cfg_data[4]
  PIN cfg_data[50]
    DIRECTION INPUT ;
    USE SIGNAL ;
    PORT
      LAYER M5 ;
        RECT  11.904 0 11.928 0.084 ;
    END
  END cfg_data[50]
  PIN cfg_data[51]
    DIRECTION INPUT ;
    USE SIGNAL ;
    PORT
      LAYER M5 ;
        RECT  12.096 0 12.12 0.084 ;
    END
  END cfg_data[51]
  PIN cfg_data[52]
    DIRECTION INPUT ;
    USE SIGNAL ;
    PORT
      LAYER M5 ;
        RECT  12.24 0 12.264 0.084 ;
    END
  END cfg_data[52]
  PIN cfg_data[53]
    DIRECTION INPUT ;
    USE SIGNAL ;
    PORT
      LAYER M5 ;
        RECT  12.432 0 12.456 0.084 ;
    END
  END cfg_data[53]
  PIN cfg_data[54]
    DIRECTION INPUT ;
    USE SIGNAL ;
    PORT
      LAYER M5 ;
        RECT  12.576 0 12.6 0.084 ;
    END
  END cfg_data[54]
  PIN cfg_data[55]
    DIRECTION INPUT ;
    USE SIGNAL ;
    PORT
      LAYER M5 ;
        RECT  12.768 0 12.792 0.084 ;
    END
  END cfg_data[55]
  PIN cfg_data[56]
    DIRECTION INPUT ;
    USE SIGNAL ;
    PORT
      LAYER M5 ;
        RECT  12.912 0 12.936 0.084 ;
    END
  END cfg_data[56]
  PIN cfg_data[57]
    DIRECTION INPUT ;
    USE SIGNAL ;
    PORT
      LAYER M5 ;
        RECT  13.104 0 13.128 0.084 ;
    END
  END cfg_data[57]
  PIN cfg_data[58]
    DIRECTION INPUT ;
    USE SIGNAL ;
    PORT
      LAYER M5 ;
        RECT  13.296 0 13.32 0.084 ;
    END
  END cfg_data[58]
  PIN cfg_data[59]
    DIRECTION INPUT ;
    USE SIGNAL ;
    PORT
      LAYER M5 ;
        RECT  13.44 0 13.464 0.084 ;
    END
  END cfg_data[59]
  PIN cfg_data[5]
    DIRECTION INPUT ;
    USE SIGNAL ;
    PORT
      LAYER M5 ;
        RECT  4.176 0 4.2 0.084 ;
    END
  END cfg_data[5]
  PIN cfg_data[60]
    DIRECTION INPUT ;
    USE SIGNAL ;
    PORT
      LAYER M5 ;
        RECT  13.632 0 13.656 0.084 ;
    END
  END cfg_data[60]
  PIN cfg_data[61]
    DIRECTION INPUT ;
    USE SIGNAL ;
    PORT
      LAYER M5 ;
        RECT  13.776 0 13.8 0.084 ;
    END
  END cfg_data[61]
  PIN cfg_data[62]
    DIRECTION INPUT ;
    USE SIGNAL ;
    PORT
      LAYER M5 ;
        RECT  13.968 0 13.992 0.084 ;
    END
  END cfg_data[62]
  PIN cfg_data[63]
    DIRECTION INPUT ;
    USE SIGNAL ;
    PORT
      LAYER M5 ;
        RECT  14.112 0 14.136 0.084 ;
    END
  END cfg_data[63]
  PIN cfg_data[64]
    DIRECTION INPUT ;
    USE SIGNAL ;
    PORT
      LAYER M5 ;
        RECT  14.304 0 14.328 0.084 ;
    END
  END cfg_data[64]
  PIN cfg_data[65]
    DIRECTION INPUT ;
    USE SIGNAL ;
    PORT
      LAYER M5 ;
        RECT  14.496 0 14.52 0.084 ;
    END
  END cfg_data[65]
  PIN cfg_data[66]
    DIRECTION INPUT ;
    USE SIGNAL ;
    PORT
      LAYER M5 ;
        RECT  14.64 0 14.664 0.084 ;
    END
  END cfg_data[66]
  PIN cfg_data[67]
    DIRECTION INPUT ;
    USE SIGNAL ;
    PORT
      LAYER M5 ;
        RECT  14.832 0 14.856 0.084 ;
    END
  END cfg_data[67]
  PIN cfg_data[68]
    DIRECTION INPUT ;
    USE SIGNAL ;
    PORT
      LAYER M5 ;
        RECT  14.976 0 15 0.084 ;
    END
  END cfg_data[68]
  PIN cfg_data[69]
    DIRECTION INPUT ;
    USE SIGNAL ;
    PORT
      LAYER M5 ;
        RECT  15.168 0 15.192 0.084 ;
    END
  END cfg_data[69]
  PIN cfg_data[6]
    DIRECTION INPUT ;
    USE SIGNAL ;
    PORT
      LAYER M5 ;
        RECT  4.32 0 4.344 0.084 ;
    END
  END cfg_data[6]
  PIN cfg_data[70]
    DIRECTION INPUT ;
    USE SIGNAL ;
    PORT
      LAYER M5 ;
        RECT  15.36 0 15.384 0.084 ;
    END
  END cfg_data[70]
  PIN cfg_data[71]
    DIRECTION INPUT ;
    USE SIGNAL ;
    PORT
      LAYER M5 ;
        RECT  15.504 0 15.528 0.084 ;
    END
  END cfg_data[71]
  PIN cfg_data[72]
    DIRECTION INPUT ;
    USE SIGNAL ;
    PORT
      LAYER M5 ;
        RECT  15.696 0 15.72 0.084 ;
    END
  END cfg_data[72]
  PIN cfg_data[73]
    DIRECTION INPUT ;
    USE SIGNAL ;
    PORT
      LAYER M5 ;
        RECT  15.84 0 15.864 0.084 ;
    END
  END cfg_data[73]
  PIN cfg_data[74]
    DIRECTION INPUT ;
    USE SIGNAL ;
    PORT
      LAYER M5 ;
        RECT  16.032 0 16.056 0.084 ;
    END
  END cfg_data[74]
  PIN cfg_data[75]
    DIRECTION INPUT ;
    USE SIGNAL ;
    PORT
      LAYER M5 ;
        RECT  16.176 0 16.2 0.084 ;
    END
  END cfg_data[75]
  PIN cfg_data[76]
    DIRECTION INPUT ;
    USE SIGNAL ;
    PORT
      LAYER M5 ;
        RECT  16.368 0 16.392 0.084 ;
    END
  END cfg_data[76]
  PIN cfg_data[77]
    DIRECTION INPUT ;
    USE SIGNAL ;
    PORT
      LAYER M5 ;
        RECT  16.56 0 16.584 0.084 ;
    END
  END cfg_data[77]
  PIN cfg_data[78]
    DIRECTION INPUT ;
    USE SIGNAL ;
    PORT
      LAYER M5 ;
        RECT  16.704 0 16.728 0.084 ;
    END
  END cfg_data[78]
  PIN cfg_data[79]
    DIRECTION INPUT ;
    USE SIGNAL ;
    PORT
      LAYER M5 ;
        RECT  16.896 0 16.92 0.084 ;
    END
  END cfg_data[79]
  PIN cfg_data[7]
    DIRECTION INPUT ;
    USE SIGNAL ;
    PORT
      LAYER M5 ;
        RECT  4.512 0 4.536 0.084 ;
    END
  END cfg_data[7]
  PIN cfg_data[80]
    DIRECTION INPUT ;
    USE SIGNAL ;
    PORT
      LAYER M5 ;
        RECT  17.04 0 17.064 0.084 ;
    END
  END cfg_data[80]
  PIN cfg_data[81]
    DIRECTION INPUT ;
    USE SIGNAL ;
    PORT
      LAYER M5 ;
        RECT  17.232 0 17.256 0.084 ;
    END
  END cfg_data[81]
  PIN cfg_data[82]
    DIRECTION INPUT ;
    USE SIGNAL ;
    PORT
      LAYER M5 ;
        RECT  17.424 0 17.448 0.084 ;
    END
  END cfg_data[82]
  PIN cfg_data[83]
    DIRECTION INPUT ;
    USE SIGNAL ;
    PORT
      LAYER M5 ;
        RECT  17.568 0 17.592 0.084 ;
    END
  END cfg_data[83]
  PIN cfg_data[84]
    DIRECTION INPUT ;
    USE SIGNAL ;
    PORT
      LAYER M5 ;
        RECT  17.76 0 17.784 0.084 ;
    END
  END cfg_data[84]
  PIN cfg_data[85]
    DIRECTION INPUT ;
    USE SIGNAL ;
    PORT
      LAYER M5 ;
        RECT  17.904 0 17.928 0.084 ;
    END
  END cfg_data[85]
  PIN cfg_data[86]
    DIRECTION INPUT ;
    USE SIGNAL ;
    PORT
      LAYER M5 ;
        RECT  18.096 0 18.12 0.084 ;
    END
  END cfg_data[86]
  PIN cfg_data[87]
    DIRECTION INPUT ;
    USE SIGNAL ;
    PORT
      LAYER M5 ;
        RECT  18.24 0 18.264 0.084 ;
    END
  END cfg_data[87]
  PIN cfg_data[88]
    DIRECTION INPUT ;
    USE SIGNAL ;
    PORT
      LAYER M5 ;
        RECT  18.432 0 18.456 0.084 ;
    END
  END cfg_data[88]
  PIN cfg_data[89]
    DIRECTION INPUT ;
    USE SIGNAL ;
    PORT
      LAYER M5 ;
        RECT  18.624 0 18.648 0.084 ;
    END
  END cfg_data[89]
  PIN cfg_data[8]
    DIRECTION INPUT ;
    USE SIGNAL ;
    PORT
      LAYER M5 ;
        RECT  4.704 0 4.728 0.084 ;
    END
  END cfg_data[8]
  PIN cfg_data[90]
    DIRECTION INPUT ;
    USE SIGNAL ;
    PORT
      LAYER M5 ;
        RECT  18.768 0 18.792 0.084 ;
    END
  END cfg_data[90]
  PIN cfg_data[91]
    DIRECTION INPUT ;
    USE SIGNAL ;
    PORT
      LAYER M5 ;
        RECT  18.96 0 18.984 0.084 ;
    END
  END cfg_data[91]
  PIN cfg_data[92]
    DIRECTION INPUT ;
    USE SIGNAL ;
    PORT
      LAYER M5 ;
        RECT  19.104 0 19.128 0.084 ;
    END
  END cfg_data[92]
  PIN cfg_data[93]
    DIRECTION INPUT ;
    USE SIGNAL ;
    PORT
      LAYER M5 ;
        RECT  19.296 0 19.32 0.084 ;
    END
  END cfg_data[93]
  PIN cfg_data[94]
    DIRECTION INPUT ;
    USE SIGNAL ;
    PORT
      LAYER M5 ;
        RECT  19.44 0 19.464 0.084 ;
    END
  END cfg_data[94]
  PIN cfg_data[95]
    DIRECTION INPUT ;
    USE SIGNAL ;
    PORT
      LAYER M5 ;
        RECT  19.632 0 19.656 0.084 ;
    END
  END cfg_data[95]
  PIN cfg_data[96]
    DIRECTION INPUT ;
    USE SIGNAL ;
    PORT
      LAYER M5 ;
        RECT  19.824 0 19.848 0.084 ;
    END
  END cfg_data[96]
  PIN cfg_data[97]
    DIRECTION INPUT ;
    USE SIGNAL ;
    PORT
      LAYER M5 ;
        RECT  19.968 0 19.992 0.084 ;
    END
  END cfg_data[97]
  PIN cfg_data[98]
    DIRECTION INPUT ;
    USE SIGNAL ;
    PORT
      LAYER M5 ;
        RECT  20.16 0 20.184 0.084 ;
    END
  END cfg_data[98]
  PIN cfg_data[99]
    DIRECTION INPUT ;
    USE SIGNAL ;
    PORT
      LAYER M5 ;
        RECT  20.304 0 20.328 0.084 ;
    END
  END cfg_data[99]
  PIN cfg_data[9]
    DIRECTION INPUT ;
    USE SIGNAL ;
    PORT
      LAYER M5 ;
        RECT  4.848 0 4.872 0.084 ;
    END
  END cfg_data[9]
  PIN cfg_target[0]
    DIRECTION INPUT ;
    USE SIGNAL ;
    PORT
      LAYER M5 ;
        RECT  47.328 0 47.352 0.084 ;
    END
  END cfg_target[0]
  PIN cfg_target[1]
    DIRECTION INPUT ;
    USE SIGNAL ;
    PORT
      LAYER M5 ;
        RECT  47.472 0 47.496 0.084 ;
    END
  END cfg_target[1]
  PIN cfg_target[2]
    DIRECTION INPUT ;
    USE SIGNAL ;
    PORT
      LAYER M5 ;
        RECT  47.664 0 47.688 0.084 ;
    END
  END cfg_target[2]
  PIN cfg_target[3]
    DIRECTION INPUT ;
    USE SIGNAL ;
    PORT
      LAYER M5 ;
        RECT  47.808 0 47.832 0.084 ;
    END
  END cfg_target[3]
  PIN cfg_target[4]
    DIRECTION INPUT ;
    USE SIGNAL ;
    PORT
      LAYER M5 ;
        RECT  48 0 48.024 0.084 ;
    END
  END cfg_target[4]
  PIN cfg_target[5]
    DIRECTION INPUT ;
    USE SIGNAL ;
    PORT
      LAYER M5 ;
        RECT  48.144 0 48.168 0.084 ;
    END
  END cfg_target[5]
  PIN cfg_target[6]
    DIRECTION INPUT ;
    USE SIGNAL ;
    PORT
      LAYER M5 ;
        RECT  48.336 0 48.36 0.084 ;
    END
  END cfg_target[6]
  PIN cfg_target[7]
    DIRECTION INPUT ;
    USE SIGNAL ;
    PORT
      LAYER M5 ;
        RECT  48.528 0 48.552 0.084 ;
    END
  END cfg_target[7]
  PIN cfg_v
    DIRECTION INPUT ;
    USE SIGNAL ;
    PORT
      LAYER M5 ;
        RECT  48.672 0 48.696 0.084 ;
    END
  END cfg_v
  PIN clk
    DIRECTION INPUT ;
    USE SIGNAL ;
    PORT
      LAYER M5 ;
        RECT  48.864 0 48.888 0.084 ;
    END
  END clk
  PIN clk_hbm
    DIRECTION INPUT ;
    USE SIGNAL ;
    PORT
      LAYER M5 ;
        RECT  1.2 51.756 1.224 51.84 ;
    END
  END clk_hbm
  PIN fault
    DIRECTION OUTPUT ;
    USE SIGNAL ;
    PORT
      LAYER M5 ;
        RECT  49.008 0 49.032 0.084 ;
    END
  END fault
  PIN pc_rst_n
    DIRECTION OUTPUT ;
    USE SIGNAL ;
    PORT
      LAYER M5 ;
        RECT  1.536 51.756 1.56 51.84 ;
    END
  END pc_rst_n
  PIN ready
    DIRECTION OUTPUT ;
    USE SIGNAL ;
    PORT
      LAYER M5 ;
        RECT  49.2 0 49.224 0.084 ;
    END
  END ready
  PIN refresh_reload[0]
    DIRECTION OUTPUT ;
    USE SIGNAL ;
    PORT
      LAYER M5 ;
        RECT  1.92 51.756 1.944 51.84 ;
    END
  END refresh_reload[0]
  PIN refresh_reload[100]
    DIRECTION OUTPUT ;
    USE SIGNAL ;
    PORT
      LAYER M5 ;
        RECT  39.984 51.756 40.008 51.84 ;
    END
  END refresh_reload[100]
  PIN refresh_reload[101]
    DIRECTION OUTPUT ;
    USE SIGNAL ;
    PORT
      LAYER M5 ;
        RECT  40.368 51.756 40.392 51.84 ;
    END
  END refresh_reload[101]
  PIN refresh_reload[102]
    DIRECTION OUTPUT ;
    USE SIGNAL ;
    PORT
      LAYER M5 ;
        RECT  40.752 51.756 40.776 51.84 ;
    END
  END refresh_reload[102]
  PIN refresh_reload[103]
    DIRECTION OUTPUT ;
    USE SIGNAL ;
    PORT
      LAYER M5 ;
        RECT  41.136 51.756 41.16 51.84 ;
    END
  END refresh_reload[103]
  PIN refresh_reload[104]
    DIRECTION OUTPUT ;
    USE SIGNAL ;
    PORT
      LAYER M5 ;
        RECT  41.52 51.756 41.544 51.84 ;
    END
  END refresh_reload[104]
  PIN refresh_reload[105]
    DIRECTION OUTPUT ;
    USE SIGNAL ;
    PORT
      LAYER M5 ;
        RECT  41.904 51.756 41.928 51.84 ;
    END
  END refresh_reload[105]
  PIN refresh_reload[106]
    DIRECTION OUTPUT ;
    USE SIGNAL ;
    PORT
      LAYER M5 ;
        RECT  42.288 51.756 42.312 51.84 ;
    END
  END refresh_reload[106]
  PIN refresh_reload[107]
    DIRECTION OUTPUT ;
    USE SIGNAL ;
    PORT
      LAYER M5 ;
        RECT  42.672 51.756 42.696 51.84 ;
    END
  END refresh_reload[107]
  PIN refresh_reload[108]
    DIRECTION OUTPUT ;
    USE SIGNAL ;
    PORT
      LAYER M5 ;
        RECT  43.008 51.756 43.032 51.84 ;
    END
  END refresh_reload[108]
  PIN refresh_reload[109]
    DIRECTION OUTPUT ;
    USE SIGNAL ;
    PORT
      LAYER M5 ;
        RECT  43.392 51.756 43.416 51.84 ;
    END
  END refresh_reload[109]
  PIN refresh_reload[10]
    DIRECTION OUTPUT ;
    USE SIGNAL ;
    PORT
      LAYER M5 ;
        RECT  5.76 51.756 5.784 51.84 ;
    END
  END refresh_reload[10]
  PIN refresh_reload[110]
    DIRECTION OUTPUT ;
    USE SIGNAL ;
    PORT
      LAYER M5 ;
        RECT  43.776 51.756 43.8 51.84 ;
    END
  END refresh_reload[110]
  PIN refresh_reload[111]
    DIRECTION OUTPUT ;
    USE SIGNAL ;
    PORT
      LAYER M5 ;
        RECT  44.16 51.756 44.184 51.84 ;
    END
  END refresh_reload[111]
  PIN refresh_reload[112]
    DIRECTION OUTPUT ;
    USE SIGNAL ;
    PORT
      LAYER M5 ;
        RECT  44.544 51.756 44.568 51.84 ;
    END
  END refresh_reload[112]
  PIN refresh_reload[113]
    DIRECTION OUTPUT ;
    USE SIGNAL ;
    PORT
      LAYER M5 ;
        RECT  44.928 51.756 44.952 51.84 ;
    END
  END refresh_reload[113]
  PIN refresh_reload[114]
    DIRECTION OUTPUT ;
    USE SIGNAL ;
    PORT
      LAYER M5 ;
        RECT  45.312 51.756 45.336 51.84 ;
    END
  END refresh_reload[114]
  PIN refresh_reload[115]
    DIRECTION OUTPUT ;
    USE SIGNAL ;
    PORT
      LAYER M5 ;
        RECT  45.696 51.756 45.72 51.84 ;
    END
  END refresh_reload[115]
  PIN refresh_reload[116]
    DIRECTION OUTPUT ;
    USE SIGNAL ;
    PORT
      LAYER M5 ;
        RECT  46.08 51.756 46.104 51.84 ;
    END
  END refresh_reload[116]
  PIN refresh_reload[117]
    DIRECTION OUTPUT ;
    USE SIGNAL ;
    PORT
      LAYER M5 ;
        RECT  46.464 51.756 46.488 51.84 ;
    END
  END refresh_reload[117]
  PIN refresh_reload[118]
    DIRECTION OUTPUT ;
    USE SIGNAL ;
    PORT
      LAYER M5 ;
        RECT  46.848 51.756 46.872 51.84 ;
    END
  END refresh_reload[118]
  PIN refresh_reload[119]
    DIRECTION OUTPUT ;
    USE SIGNAL ;
    PORT
      LAYER M5 ;
        RECT  47.232 51.756 47.256 51.84 ;
    END
  END refresh_reload[119]
  PIN refresh_reload[11]
    DIRECTION OUTPUT ;
    USE SIGNAL ;
    PORT
      LAYER M5 ;
        RECT  6.144 51.756 6.168 51.84 ;
    END
  END refresh_reload[11]
  PIN refresh_reload[120]
    DIRECTION OUTPUT ;
    USE SIGNAL ;
    PORT
      LAYER M5 ;
        RECT  47.616 51.756 47.64 51.84 ;
    END
  END refresh_reload[120]
  PIN refresh_reload[121]
    DIRECTION OUTPUT ;
    USE SIGNAL ;
    PORT
      LAYER M5 ;
        RECT  47.952 51.756 47.976 51.84 ;
    END
  END refresh_reload[121]
  PIN refresh_reload[122]
    DIRECTION OUTPUT ;
    USE SIGNAL ;
    PORT
      LAYER M5 ;
        RECT  48.336 51.756 48.36 51.84 ;
    END
  END refresh_reload[122]
  PIN refresh_reload[123]
    DIRECTION OUTPUT ;
    USE SIGNAL ;
    PORT
      LAYER M5 ;
        RECT  48.72 51.756 48.744 51.84 ;
    END
  END refresh_reload[123]
  PIN refresh_reload[124]
    DIRECTION OUTPUT ;
    USE SIGNAL ;
    PORT
      LAYER M5 ;
        RECT  49.104 51.756 49.128 51.84 ;
    END
  END refresh_reload[124]
  PIN refresh_reload[125]
    DIRECTION OUTPUT ;
    USE SIGNAL ;
    PORT
      LAYER M5 ;
        RECT  49.488 51.756 49.512 51.84 ;
    END
  END refresh_reload[125]
  PIN refresh_reload[126]
    DIRECTION OUTPUT ;
    USE SIGNAL ;
    PORT
      LAYER M5 ;
        RECT  49.872 51.756 49.896 51.84 ;
    END
  END refresh_reload[126]
  PIN refresh_reload[127]
    DIRECTION OUTPUT ;
    USE SIGNAL ;
    PORT
      LAYER M5 ;
        RECT  50.256 51.756 50.28 51.84 ;
    END
  END refresh_reload[127]
  PIN refresh_reload[12]
    DIRECTION OUTPUT ;
    USE SIGNAL ;
    PORT
      LAYER M5 ;
        RECT  6.528 51.756 6.552 51.84 ;
    END
  END refresh_reload[12]
  PIN refresh_reload[13]
    DIRECTION OUTPUT ;
    USE SIGNAL ;
    PORT
      LAYER M5 ;
        RECT  6.864 51.756 6.888 51.84 ;
    END
  END refresh_reload[13]
  PIN refresh_reload[14]
    DIRECTION OUTPUT ;
    USE SIGNAL ;
    PORT
      LAYER M5 ;
        RECT  7.248 51.756 7.272 51.84 ;
    END
  END refresh_reload[14]
  PIN refresh_reload[15]
    DIRECTION OUTPUT ;
    USE SIGNAL ;
    PORT
      LAYER M5 ;
        RECT  7.632 51.756 7.656 51.84 ;
    END
  END refresh_reload[15]
  PIN refresh_reload[16]
    DIRECTION OUTPUT ;
    USE SIGNAL ;
    PORT
      LAYER M5 ;
        RECT  8.016 51.756 8.04 51.84 ;
    END
  END refresh_reload[16]
  PIN refresh_reload[17]
    DIRECTION OUTPUT ;
    USE SIGNAL ;
    PORT
      LAYER M5 ;
        RECT  8.4 51.756 8.424 51.84 ;
    END
  END refresh_reload[17]
  PIN refresh_reload[18]
    DIRECTION OUTPUT ;
    USE SIGNAL ;
    PORT
      LAYER M5 ;
        RECT  8.784 51.756 8.808 51.84 ;
    END
  END refresh_reload[18]
  PIN refresh_reload[19]
    DIRECTION OUTPUT ;
    USE SIGNAL ;
    PORT
      LAYER M5 ;
        RECT  9.168 51.756 9.192 51.84 ;
    END
  END refresh_reload[19]
  PIN refresh_reload[1]
    DIRECTION OUTPUT ;
    USE SIGNAL ;
    PORT
      LAYER M5 ;
        RECT  2.304 51.756 2.328 51.84 ;
    END
  END refresh_reload[1]
  PIN refresh_reload[20]
    DIRECTION OUTPUT ;
    USE SIGNAL ;
    PORT
      LAYER M5 ;
        RECT  9.552 51.756 9.576 51.84 ;
    END
  END refresh_reload[20]
  PIN refresh_reload[21]
    DIRECTION OUTPUT ;
    USE SIGNAL ;
    PORT
      LAYER M5 ;
        RECT  9.936 51.756 9.96 51.84 ;
    END
  END refresh_reload[21]
  PIN refresh_reload[22]
    DIRECTION OUTPUT ;
    USE SIGNAL ;
    PORT
      LAYER M5 ;
        RECT  10.32 51.756 10.344 51.84 ;
    END
  END refresh_reload[22]
  PIN refresh_reload[23]
    DIRECTION OUTPUT ;
    USE SIGNAL ;
    PORT
      LAYER M5 ;
        RECT  10.704 51.756 10.728 51.84 ;
    END
  END refresh_reload[23]
  PIN refresh_reload[24]
    DIRECTION OUTPUT ;
    USE SIGNAL ;
    PORT
      LAYER M5 ;
        RECT  11.088 51.756 11.112 51.84 ;
    END
  END refresh_reload[24]
  PIN refresh_reload[25]
    DIRECTION OUTPUT ;
    USE SIGNAL ;
    PORT
      LAYER M5 ;
        RECT  11.472 51.756 11.496 51.84 ;
    END
  END refresh_reload[25]
  PIN refresh_reload[26]
    DIRECTION OUTPUT ;
    USE SIGNAL ;
    PORT
      LAYER M5 ;
        RECT  11.808 51.756 11.832 51.84 ;
    END
  END refresh_reload[26]
  PIN refresh_reload[27]
    DIRECTION OUTPUT ;
    USE SIGNAL ;
    PORT
      LAYER M5 ;
        RECT  12.192 51.756 12.216 51.84 ;
    END
  END refresh_reload[27]
  PIN refresh_reload[28]
    DIRECTION OUTPUT ;
    USE SIGNAL ;
    PORT
      LAYER M5 ;
        RECT  12.576 51.756 12.6 51.84 ;
    END
  END refresh_reload[28]
  PIN refresh_reload[29]
    DIRECTION OUTPUT ;
    USE SIGNAL ;
    PORT
      LAYER M5 ;
        RECT  12.96 51.756 12.984 51.84 ;
    END
  END refresh_reload[29]
  PIN refresh_reload[2]
    DIRECTION OUTPUT ;
    USE SIGNAL ;
    PORT
      LAYER M5 ;
        RECT  2.688 51.756 2.712 51.84 ;
    END
  END refresh_reload[2]
  PIN refresh_reload[30]
    DIRECTION OUTPUT ;
    USE SIGNAL ;
    PORT
      LAYER M5 ;
        RECT  13.344 51.756 13.368 51.84 ;
    END
  END refresh_reload[30]
  PIN refresh_reload[31]
    DIRECTION OUTPUT ;
    USE SIGNAL ;
    PORT
      LAYER M5 ;
        RECT  13.728 51.756 13.752 51.84 ;
    END
  END refresh_reload[31]
  PIN refresh_reload[32]
    DIRECTION OUTPUT ;
    USE SIGNAL ;
    PORT
      LAYER M5 ;
        RECT  14.112 51.756 14.136 51.84 ;
    END
  END refresh_reload[32]
  PIN refresh_reload[33]
    DIRECTION OUTPUT ;
    USE SIGNAL ;
    PORT
      LAYER M5 ;
        RECT  14.496 51.756 14.52 51.84 ;
    END
  END refresh_reload[33]
  PIN refresh_reload[34]
    DIRECTION OUTPUT ;
    USE SIGNAL ;
    PORT
      LAYER M5 ;
        RECT  14.88 51.756 14.904 51.84 ;
    END
  END refresh_reload[34]
  PIN refresh_reload[35]
    DIRECTION OUTPUT ;
    USE SIGNAL ;
    PORT
      LAYER M5 ;
        RECT  15.264 51.756 15.288 51.84 ;
    END
  END refresh_reload[35]
  PIN refresh_reload[36]
    DIRECTION OUTPUT ;
    USE SIGNAL ;
    PORT
      LAYER M5 ;
        RECT  15.648 51.756 15.672 51.84 ;
    END
  END refresh_reload[36]
  PIN refresh_reload[37]
    DIRECTION OUTPUT ;
    USE SIGNAL ;
    PORT
      LAYER M5 ;
        RECT  16.032 51.756 16.056 51.84 ;
    END
  END refresh_reload[37]
  PIN refresh_reload[38]
    DIRECTION OUTPUT ;
    USE SIGNAL ;
    PORT
      LAYER M5 ;
        RECT  16.416 51.756 16.44 51.84 ;
    END
  END refresh_reload[38]
  PIN refresh_reload[39]
    DIRECTION OUTPUT ;
    USE SIGNAL ;
    PORT
      LAYER M5 ;
        RECT  16.8 51.756 16.824 51.84 ;
    END
  END refresh_reload[39]
  PIN refresh_reload[3]
    DIRECTION OUTPUT ;
    USE SIGNAL ;
    PORT
      LAYER M5 ;
        RECT  3.072 51.756 3.096 51.84 ;
    END
  END refresh_reload[3]
  PIN refresh_reload[40]
    DIRECTION OUTPUT ;
    USE SIGNAL ;
    PORT
      LAYER M5 ;
        RECT  17.136 51.756 17.16 51.84 ;
    END
  END refresh_reload[40]
  PIN refresh_reload[41]
    DIRECTION OUTPUT ;
    USE SIGNAL ;
    PORT
      LAYER M5 ;
        RECT  17.52 51.756 17.544 51.84 ;
    END
  END refresh_reload[41]
  PIN refresh_reload[42]
    DIRECTION OUTPUT ;
    USE SIGNAL ;
    PORT
      LAYER M5 ;
        RECT  17.904 51.756 17.928 51.84 ;
    END
  END refresh_reload[42]
  PIN refresh_reload[43]
    DIRECTION OUTPUT ;
    USE SIGNAL ;
    PORT
      LAYER M5 ;
        RECT  18.288 51.756 18.312 51.84 ;
    END
  END refresh_reload[43]
  PIN refresh_reload[44]
    DIRECTION OUTPUT ;
    USE SIGNAL ;
    PORT
      LAYER M5 ;
        RECT  18.672 51.756 18.696 51.84 ;
    END
  END refresh_reload[44]
  PIN refresh_reload[45]
    DIRECTION OUTPUT ;
    USE SIGNAL ;
    PORT
      LAYER M5 ;
        RECT  19.056 51.756 19.08 51.84 ;
    END
  END refresh_reload[45]
  PIN refresh_reload[46]
    DIRECTION OUTPUT ;
    USE SIGNAL ;
    PORT
      LAYER M5 ;
        RECT  19.44 51.756 19.464 51.84 ;
    END
  END refresh_reload[46]
  PIN refresh_reload[47]
    DIRECTION OUTPUT ;
    USE SIGNAL ;
    PORT
      LAYER M5 ;
        RECT  19.824 51.756 19.848 51.84 ;
    END
  END refresh_reload[47]
  PIN refresh_reload[48]
    DIRECTION OUTPUT ;
    USE SIGNAL ;
    PORT
      LAYER M5 ;
        RECT  20.208 51.756 20.232 51.84 ;
    END
  END refresh_reload[48]
  PIN refresh_reload[49]
    DIRECTION OUTPUT ;
    USE SIGNAL ;
    PORT
      LAYER M5 ;
        RECT  20.592 51.756 20.616 51.84 ;
    END
  END refresh_reload[49]
  PIN refresh_reload[4]
    DIRECTION OUTPUT ;
    USE SIGNAL ;
    PORT
      LAYER M5 ;
        RECT  3.456 51.756 3.48 51.84 ;
    END
  END refresh_reload[4]
  PIN refresh_reload[50]
    DIRECTION OUTPUT ;
    USE SIGNAL ;
    PORT
      LAYER M5 ;
        RECT  20.976 51.756 21 51.84 ;
    END
  END refresh_reload[50]
  PIN refresh_reload[51]
    DIRECTION OUTPUT ;
    USE SIGNAL ;
    PORT
      LAYER M5 ;
        RECT  21.36 51.756 21.384 51.84 ;
    END
  END refresh_reload[51]
  PIN refresh_reload[52]
    DIRECTION OUTPUT ;
    USE SIGNAL ;
    PORT
      LAYER M5 ;
        RECT  21.744 51.756 21.768 51.84 ;
    END
  END refresh_reload[52]
  PIN refresh_reload[53]
    DIRECTION OUTPUT ;
    USE SIGNAL ;
    PORT
      LAYER M5 ;
        RECT  22.08 51.756 22.104 51.84 ;
    END
  END refresh_reload[53]
  PIN refresh_reload[54]
    DIRECTION OUTPUT ;
    USE SIGNAL ;
    PORT
      LAYER M5 ;
        RECT  22.464 51.756 22.488 51.84 ;
    END
  END refresh_reload[54]
  PIN refresh_reload[55]
    DIRECTION OUTPUT ;
    USE SIGNAL ;
    PORT
      LAYER M5 ;
        RECT  22.848 51.756 22.872 51.84 ;
    END
  END refresh_reload[55]
  PIN refresh_reload[56]
    DIRECTION OUTPUT ;
    USE SIGNAL ;
    PORT
      LAYER M5 ;
        RECT  23.232 51.756 23.256 51.84 ;
    END
  END refresh_reload[56]
  PIN refresh_reload[57]
    DIRECTION OUTPUT ;
    USE SIGNAL ;
    PORT
      LAYER M5 ;
        RECT  23.616 51.756 23.64 51.84 ;
    END
  END refresh_reload[57]
  PIN refresh_reload[58]
    DIRECTION OUTPUT ;
    USE SIGNAL ;
    PORT
      LAYER M5 ;
        RECT  24 51.756 24.024 51.84 ;
    END
  END refresh_reload[58]
  PIN refresh_reload[59]
    DIRECTION OUTPUT ;
    USE SIGNAL ;
    PORT
      LAYER M5 ;
        RECT  24.384 51.756 24.408 51.84 ;
    END
  END refresh_reload[59]
  PIN refresh_reload[5]
    DIRECTION OUTPUT ;
    USE SIGNAL ;
    PORT
      LAYER M5 ;
        RECT  3.84 51.756 3.864 51.84 ;
    END
  END refresh_reload[5]
  PIN refresh_reload[60]
    DIRECTION OUTPUT ;
    USE SIGNAL ;
    PORT
      LAYER M5 ;
        RECT  24.768 51.756 24.792 51.84 ;
    END
  END refresh_reload[60]
  PIN refresh_reload[61]
    DIRECTION OUTPUT ;
    USE SIGNAL ;
    PORT
      LAYER M5 ;
        RECT  25.152 51.756 25.176 51.84 ;
    END
  END refresh_reload[61]
  PIN refresh_reload[62]
    DIRECTION OUTPUT ;
    USE SIGNAL ;
    PORT
      LAYER M5 ;
        RECT  25.536 51.756 25.56 51.84 ;
    END
  END refresh_reload[62]
  PIN refresh_reload[63]
    DIRECTION OUTPUT ;
    USE SIGNAL ;
    PORT
      LAYER M5 ;
        RECT  25.92 51.756 25.944 51.84 ;
    END
  END refresh_reload[63]
  PIN refresh_reload[64]
    DIRECTION OUTPUT ;
    USE SIGNAL ;
    PORT
      LAYER M5 ;
        RECT  26.304 51.756 26.328 51.84 ;
    END
  END refresh_reload[64]
  PIN refresh_reload[65]
    DIRECTION OUTPUT ;
    USE SIGNAL ;
    PORT
      LAYER M5 ;
        RECT  26.688 51.756 26.712 51.84 ;
    END
  END refresh_reload[65]
  PIN refresh_reload[66]
    DIRECTION OUTPUT ;
    USE SIGNAL ;
    PORT
      LAYER M5 ;
        RECT  27.072 51.756 27.096 51.84 ;
    END
  END refresh_reload[66]
  PIN refresh_reload[67]
    DIRECTION OUTPUT ;
    USE SIGNAL ;
    PORT
      LAYER M5 ;
        RECT  27.408 51.756 27.432 51.84 ;
    END
  END refresh_reload[67]
  PIN refresh_reload[68]
    DIRECTION OUTPUT ;
    USE SIGNAL ;
    PORT
      LAYER M5 ;
        RECT  27.792 51.756 27.816 51.84 ;
    END
  END refresh_reload[68]
  PIN refresh_reload[69]
    DIRECTION OUTPUT ;
    USE SIGNAL ;
    PORT
      LAYER M5 ;
        RECT  28.176 51.756 28.2 51.84 ;
    END
  END refresh_reload[69]
  PIN refresh_reload[6]
    DIRECTION OUTPUT ;
    USE SIGNAL ;
    PORT
      LAYER M5 ;
        RECT  4.224 51.756 4.248 51.84 ;
    END
  END refresh_reload[6]
  PIN refresh_reload[70]
    DIRECTION OUTPUT ;
    USE SIGNAL ;
    PORT
      LAYER M5 ;
        RECT  28.56 51.756 28.584 51.84 ;
    END
  END refresh_reload[70]
  PIN refresh_reload[71]
    DIRECTION OUTPUT ;
    USE SIGNAL ;
    PORT
      LAYER M5 ;
        RECT  28.944 51.756 28.968 51.84 ;
    END
  END refresh_reload[71]
  PIN refresh_reload[72]
    DIRECTION OUTPUT ;
    USE SIGNAL ;
    PORT
      LAYER M5 ;
        RECT  29.328 51.756 29.352 51.84 ;
    END
  END refresh_reload[72]
  PIN refresh_reload[73]
    DIRECTION OUTPUT ;
    USE SIGNAL ;
    PORT
      LAYER M5 ;
        RECT  29.712 51.756 29.736 51.84 ;
    END
  END refresh_reload[73]
  PIN refresh_reload[74]
    DIRECTION OUTPUT ;
    USE SIGNAL ;
    PORT
      LAYER M5 ;
        RECT  30.096 51.756 30.12 51.84 ;
    END
  END refresh_reload[74]
  PIN refresh_reload[75]
    DIRECTION OUTPUT ;
    USE SIGNAL ;
    PORT
      LAYER M5 ;
        RECT  30.48 51.756 30.504 51.84 ;
    END
  END refresh_reload[75]
  PIN refresh_reload[76]
    DIRECTION OUTPUT ;
    USE SIGNAL ;
    PORT
      LAYER M5 ;
        RECT  30.864 51.756 30.888 51.84 ;
    END
  END refresh_reload[76]
  PIN refresh_reload[77]
    DIRECTION OUTPUT ;
    USE SIGNAL ;
    PORT
      LAYER M5 ;
        RECT  31.248 51.756 31.272 51.84 ;
    END
  END refresh_reload[77]
  PIN refresh_reload[78]
    DIRECTION OUTPUT ;
    USE SIGNAL ;
    PORT
      LAYER M5 ;
        RECT  31.632 51.756 31.656 51.84 ;
    END
  END refresh_reload[78]
  PIN refresh_reload[79]
    DIRECTION OUTPUT ;
    USE SIGNAL ;
    PORT
      LAYER M5 ;
        RECT  32.016 51.756 32.04 51.84 ;
    END
  END refresh_reload[79]
  PIN refresh_reload[7]
    DIRECTION OUTPUT ;
    USE SIGNAL ;
    PORT
      LAYER M5 ;
        RECT  4.608 51.756 4.632 51.84 ;
    END
  END refresh_reload[7]
  PIN refresh_reload[80]
    DIRECTION OUTPUT ;
    USE SIGNAL ;
    PORT
      LAYER M5 ;
        RECT  32.4 51.756 32.424 51.84 ;
    END
  END refresh_reload[80]
  PIN refresh_reload[81]
    DIRECTION OUTPUT ;
    USE SIGNAL ;
    PORT
      LAYER M5 ;
        RECT  32.736 51.756 32.76 51.84 ;
    END
  END refresh_reload[81]
  PIN refresh_reload[82]
    DIRECTION OUTPUT ;
    USE SIGNAL ;
    PORT
      LAYER M5 ;
        RECT  33.12 51.756 33.144 51.84 ;
    END
  END refresh_reload[82]
  PIN refresh_reload[83]
    DIRECTION OUTPUT ;
    USE SIGNAL ;
    PORT
      LAYER M5 ;
        RECT  33.504 51.756 33.528 51.84 ;
    END
  END refresh_reload[83]
  PIN refresh_reload[84]
    DIRECTION OUTPUT ;
    USE SIGNAL ;
    PORT
      LAYER M5 ;
        RECT  33.888 51.756 33.912 51.84 ;
    END
  END refresh_reload[84]
  PIN refresh_reload[85]
    DIRECTION OUTPUT ;
    USE SIGNAL ;
    PORT
      LAYER M5 ;
        RECT  34.272 51.756 34.296 51.84 ;
    END
  END refresh_reload[85]
  PIN refresh_reload[86]
    DIRECTION OUTPUT ;
    USE SIGNAL ;
    PORT
      LAYER M5 ;
        RECT  34.656 51.756 34.68 51.84 ;
    END
  END refresh_reload[86]
  PIN refresh_reload[87]
    DIRECTION OUTPUT ;
    USE SIGNAL ;
    PORT
      LAYER M5 ;
        RECT  35.04 51.756 35.064 51.84 ;
    END
  END refresh_reload[87]
  PIN refresh_reload[88]
    DIRECTION OUTPUT ;
    USE SIGNAL ;
    PORT
      LAYER M5 ;
        RECT  35.424 51.756 35.448 51.84 ;
    END
  END refresh_reload[88]
  PIN refresh_reload[89]
    DIRECTION OUTPUT ;
    USE SIGNAL ;
    PORT
      LAYER M5 ;
        RECT  35.808 51.756 35.832 51.84 ;
    END
  END refresh_reload[89]
  PIN refresh_reload[8]
    DIRECTION OUTPUT ;
    USE SIGNAL ;
    PORT
      LAYER M5 ;
        RECT  4.992 51.756 5.016 51.84 ;
    END
  END refresh_reload[8]
  PIN refresh_reload[90]
    DIRECTION OUTPUT ;
    USE SIGNAL ;
    PORT
      LAYER M5 ;
        RECT  36.192 51.756 36.216 51.84 ;
    END
  END refresh_reload[90]
  PIN refresh_reload[91]
    DIRECTION OUTPUT ;
    USE SIGNAL ;
    PORT
      LAYER M5 ;
        RECT  36.576 51.756 36.6 51.84 ;
    END
  END refresh_reload[91]
  PIN refresh_reload[92]
    DIRECTION OUTPUT ;
    USE SIGNAL ;
    PORT
      LAYER M5 ;
        RECT  36.96 51.756 36.984 51.84 ;
    END
  END refresh_reload[92]
  PIN refresh_reload[93]
    DIRECTION OUTPUT ;
    USE SIGNAL ;
    PORT
      LAYER M5 ;
        RECT  37.344 51.756 37.368 51.84 ;
    END
  END refresh_reload[93]
  PIN refresh_reload[94]
    DIRECTION OUTPUT ;
    USE SIGNAL ;
    PORT
      LAYER M5 ;
        RECT  37.68 51.756 37.704 51.84 ;
    END
  END refresh_reload[94]
  PIN refresh_reload[95]
    DIRECTION OUTPUT ;
    USE SIGNAL ;
    PORT
      LAYER M5 ;
        RECT  38.064 51.756 38.088 51.84 ;
    END
  END refresh_reload[95]
  PIN refresh_reload[96]
    DIRECTION OUTPUT ;
    USE SIGNAL ;
    PORT
      LAYER M5 ;
        RECT  38.448 51.756 38.472 51.84 ;
    END
  END refresh_reload[96]
  PIN refresh_reload[97]
    DIRECTION OUTPUT ;
    USE SIGNAL ;
    PORT
      LAYER M5 ;
        RECT  38.832 51.756 38.856 51.84 ;
    END
  END refresh_reload[97]
  PIN refresh_reload[98]
    DIRECTION OUTPUT ;
    USE SIGNAL ;
    PORT
      LAYER M5 ;
        RECT  39.216 51.756 39.24 51.84 ;
    END
  END refresh_reload[98]
  PIN refresh_reload[99]
    DIRECTION OUTPUT ;
    USE SIGNAL ;
    PORT
      LAYER M5 ;
        RECT  39.6 51.756 39.624 51.84 ;
    END
  END refresh_reload[99]
  PIN refresh_reload[9]
    DIRECTION OUTPUT ;
    USE SIGNAL ;
    PORT
      LAYER M5 ;
        RECT  5.376 51.756 5.4 51.84 ;
    END
  END refresh_reload[9]
  PIN rst_hbm_n
    DIRECTION INPUT ;
    USE SIGNAL ;
    PORT
      LAYER M5 ;
        RECT  50.64 51.756 50.664 51.84 ;
    END
  END rst_hbm_n
  PIN rst_n
    DIRECTION INPUT ;
    USE SIGNAL ;
    PORT
      LAYER M5 ;
        RECT  49.344 0 49.368 0.084 ;
    END
  END rst_n
  PIN tgt[0]
    DIRECTION INPUT ;
    USE SIGNAL ;
    PORT
      LAYER M5 ;
        RECT  49.536 0 49.56 0.084 ;
    END
  END tgt[0]
  PIN tgt[1]
    DIRECTION INPUT ;
    USE SIGNAL ;
    PORT
      LAYER M5 ;
        RECT  49.728 0 49.752 0.084 ;
    END
  END tgt[1]
  PIN tgt[2]
    DIRECTION INPUT ;
    USE SIGNAL ;
    PORT
      LAYER M5 ;
        RECT  49.872 0 49.896 0.084 ;
    END
  END tgt[2]
  PIN tgt[3]
    DIRECTION INPUT ;
    USE SIGNAL ;
    PORT
      LAYER M5 ;
        RECT  50.064 0 50.088 0.084 ;
    END
  END tgt[3]
  PIN tgt[4]
    DIRECTION INPUT ;
    USE SIGNAL ;
    PORT
      LAYER M5 ;
        RECT  50.208 0 50.232 0.084 ;
    END
  END tgt[4]
  PIN tgt[5]
    DIRECTION INPUT ;
    USE SIGNAL ;
    PORT
      LAYER M5 ;
        RECT  50.4 0 50.424 0.084 ;
    END
  END tgt[5]
  PIN tgt[6]
    DIRECTION INPUT ;
    USE SIGNAL ;
    PORT
      LAYER M5 ;
        RECT  50.592 0 50.616 0.084 ;
    END
  END tgt[6]
  PIN tgt[7]
    DIRECTION INPUT ;
    USE SIGNAL ;
    PORT
      LAYER M5 ;
        RECT  50.736 0 50.76 0.084 ;
    END
  END tgt[7]
  PIN VDD
    DIRECTION INOUT ;
    USE POWER ;
    PORT
      LAYER M5 ;
        RECT  45.792 2.151 45.912 49.689 ;
        RECT  40.392 2.151 40.512 49.689 ;
        RECT  34.992 2.151 35.112 49.689 ;
        RECT  29.592 2.151 29.712 49.689 ;
        RECT  24.192 2.151 24.312 49.689 ;
        RECT  18.792 2.151 18.912 49.689 ;
        RECT  13.392 2.151 13.512 49.689 ;
        RECT  7.992 2.151 8.112 49.689 ;
        RECT  2.592 2.151 2.712 49.689 ;
    END
  END VDD
  PIN VSS
    DIRECTION INOUT ;
    USE GROUND ;
    PORT
      LAYER M5 ;
        RECT  45.6 2.137 45.72 49.703 ;
        RECT  40.2 2.137 40.32 49.703 ;
        RECT  34.8 2.137 34.92 49.703 ;
        RECT  29.4 2.137 29.52 49.703 ;
        RECT  24 2.137 24.12 49.703 ;
        RECT  18.6 2.137 18.72 49.703 ;
        RECT  13.2 2.137 13.32 49.703 ;
        RECT  7.8 2.137 7.92 49.703 ;
        RECT  2.4 2.137 2.52 49.703 ;
    END
  END VSS
  OBS
    LAYER RVTN ;
     RECT  2.16 2.16 49.68 2.295 ;
     RECT  2.16 2.565 49.68 2.835 ;
     RECT  2.16 3.105 49.68 3.375 ;
     RECT  2.16 3.645 49.68 3.915 ;
     RECT  2.16 4.185 49.68 4.455 ;
     RECT  2.16 4.725 49.68 4.995 ;
     RECT  2.16 5.265 49.68 5.535 ;
     RECT  2.16 5.805 49.68 6.075 ;
     RECT  2.16 6.345 49.68 6.615 ;
     RECT  2.16 6.885 49.68 7.155 ;
     RECT  2.16 7.425 49.68 7.695 ;
     RECT  2.16 7.965 49.68 8.235 ;
     RECT  2.16 8.505 49.68 8.775 ;
     RECT  2.16 9.045 49.68 9.315 ;
     RECT  2.16 9.585 49.68 9.855 ;
     RECT  2.16 10.125 49.68 10.395 ;
     RECT  2.16 10.665 49.68 10.935 ;
     RECT  2.16 11.205 49.68 11.475 ;
     RECT  2.16 11.745 49.68 12.015 ;
     RECT  2.16 12.285 49.68 12.555 ;
     RECT  2.16 12.825 49.68 13.095 ;
     RECT  2.16 13.365 49.68 13.635 ;
     RECT  2.16 13.905 49.68 14.175 ;
     RECT  2.16 14.445 49.68 14.715 ;
     RECT  2.16 14.985 49.68 15.255 ;
     RECT  2.16 15.525 49.68 15.795 ;
     RECT  2.16 16.065 49.68 16.335 ;
     RECT  2.16 16.605 49.68 16.875 ;
     RECT  2.16 17.145 49.68 17.415 ;
     RECT  2.16 17.685 49.68 17.955 ;
     RECT  2.16 18.225 49.68 18.495 ;
     RECT  2.16 18.765 49.68 19.035 ;
     RECT  2.16 19.305 49.68 19.575 ;
     RECT  2.16 19.845 49.68 20.115 ;
     RECT  2.16 20.385 49.68 20.655 ;
     RECT  2.16 20.925 49.68 21.195 ;
     RECT  2.16 21.465 49.68 21.735 ;
     RECT  2.16 22.005 49.68 22.275 ;
     RECT  2.16 22.545 49.68 22.815 ;
     RECT  2.16 23.085 49.68 23.355 ;
     RECT  2.16 23.625 49.68 23.895 ;
     RECT  2.16 24.165 49.68 24.435 ;
     RECT  2.16 24.705 49.68 24.975 ;
     RECT  2.16 25.245 49.68 25.515 ;
     RECT  2.16 25.785 49.68 26.055 ;
     RECT  2.16 26.325 49.68 26.595 ;
     RECT  2.16 26.865 49.68 27.135 ;
     RECT  2.16 27.405 49.68 27.675 ;
     RECT  2.16 27.945 49.68 28.215 ;
     RECT  2.16 28.485 49.68 28.755 ;
     RECT  2.16 29.025 49.68 29.295 ;
     RECT  2.16 29.565 49.68 29.835 ;
     RECT  2.16 30.105 49.68 30.375 ;
     RECT  2.16 30.645 49.68 30.915 ;
     RECT  2.16 31.185 49.68 31.455 ;
     RECT  2.16 31.725 49.68 31.995 ;
     RECT  2.16 32.265 49.68 32.535 ;
     RECT  2.16 32.805 49.68 33.075 ;
     RECT  2.16 33.345 49.68 33.615 ;
     RECT  2.16 33.885 49.68 34.155 ;
     RECT  2.16 34.425 49.68 34.695 ;
     RECT  2.16 34.965 49.68 35.235 ;
     RECT  2.16 35.505 49.68 35.775 ;
     RECT  2.16 36.045 49.68 36.315 ;
     RECT  2.16 36.585 49.68 36.855 ;
     RECT  2.16 37.125 49.68 37.395 ;
     RECT  2.16 37.665 49.68 37.935 ;
     RECT  2.16 38.205 49.68 38.475 ;
     RECT  2.16 38.745 49.68 39.015 ;
     RECT  2.16 39.285 49.68 39.555 ;
     RECT  2.16 39.825 49.68 40.095 ;
     RECT  2.16 40.365 49.68 40.635 ;
     RECT  2.16 40.905 49.68 41.175 ;
     RECT  2.16 41.445 49.68 41.715 ;
     RECT  2.16 41.985 49.68 42.255 ;
     RECT  2.16 42.525 49.68 42.795 ;
     RECT  2.16 43.065 49.68 43.335 ;
     RECT  2.16 43.605 49.68 43.875 ;
     RECT  2.16 44.145 49.68 44.415 ;
     RECT  2.16 44.685 49.68 44.955 ;
     RECT  2.16 45.225 49.68 45.495 ;
     RECT  2.16 45.765 49.68 46.035 ;
     RECT  2.16 46.305 49.68 46.575 ;
     RECT  2.16 46.845 49.68 47.115 ;
     RECT  2.16 47.385 49.68 47.655 ;
     RECT  2.16 47.925 49.68 48.195 ;
     RECT  2.16 48.465 49.68 48.735 ;
     RECT  2.16 49.005 49.68 49.275 ;
     RECT  2.16 49.545 49.68 49.68 ;
    LAYER RVTP ;
     RECT  2.16 2.295 49.68 2.565 ;
     RECT  2.16 2.835 49.68 3.105 ;
     RECT  2.16 3.375 49.68 3.645 ;
     RECT  2.16 3.915 49.68 4.185 ;
     RECT  2.16 4.455 49.68 4.725 ;
     RECT  2.16 4.995 49.68 5.265 ;
     RECT  2.16 5.535 49.68 5.805 ;
     RECT  2.16 6.075 49.68 6.345 ;
     RECT  2.16 6.615 49.68 6.885 ;
     RECT  2.16 7.155 49.68 7.425 ;
     RECT  2.16 7.695 49.68 7.965 ;
     RECT  2.16 8.235 49.68 8.505 ;
     RECT  2.16 8.775 49.68 9.045 ;
     RECT  2.16 9.315 49.68 9.585 ;
     RECT  2.16 9.855 49.68 10.125 ;
     RECT  2.16 10.395 49.68 10.665 ;
     RECT  2.16 10.935 49.68 11.205 ;
     RECT  2.16 11.475 49.68 11.745 ;
     RECT  2.16 12.015 49.68 12.285 ;
     RECT  2.16 12.555 49.68 12.825 ;
     RECT  2.16 13.095 49.68 13.365 ;
     RECT  2.16 13.635 49.68 13.905 ;
     RECT  2.16 14.175 49.68 14.445 ;
     RECT  2.16 14.715 49.68 14.985 ;
     RECT  2.16 15.255 49.68 15.525 ;
     RECT  2.16 15.795 49.68 16.065 ;
     RECT  2.16 16.335 49.68 16.605 ;
     RECT  2.16 16.875 49.68 17.145 ;
     RECT  2.16 17.415 49.68 17.685 ;
     RECT  2.16 17.955 49.68 18.225 ;
     RECT  2.16 18.495 49.68 18.765 ;
     RECT  2.16 19.035 49.68 19.305 ;
     RECT  2.16 19.575 49.68 19.845 ;
     RECT  2.16 20.115 49.68 20.385 ;
     RECT  2.16 20.655 49.68 20.925 ;
     RECT  2.16 21.195 49.68 21.465 ;
     RECT  2.16 21.735 49.68 22.005 ;
     RECT  2.16 22.275 49.68 22.545 ;
     RECT  2.16 22.815 49.68 23.085 ;
     RECT  2.16 23.355 49.68 23.625 ;
     RECT  2.16 23.895 49.68 24.165 ;
     RECT  2.16 24.435 49.68 24.705 ;
     RECT  2.16 24.975 49.68 25.245 ;
     RECT  2.16 25.515 49.68 25.785 ;
     RECT  2.16 26.055 49.68 26.325 ;
     RECT  2.16 26.595 49.68 26.865 ;
     RECT  2.16 27.135 49.68 27.405 ;
     RECT  2.16 27.675 49.68 27.945 ;
     RECT  2.16 28.215 49.68 28.485 ;
     RECT  2.16 28.755 49.68 29.025 ;
     RECT  2.16 29.295 49.68 29.565 ;
     RECT  2.16 29.835 49.68 30.105 ;
     RECT  2.16 30.375 49.68 30.645 ;
     RECT  2.16 30.915 49.68 31.185 ;
     RECT  2.16 31.455 49.68 31.725 ;
     RECT  2.16 31.995 49.68 32.265 ;
     RECT  2.16 32.535 49.68 32.805 ;
     RECT  2.16 33.075 49.68 33.345 ;
     RECT  2.16 33.615 49.68 33.885 ;
     RECT  2.16 34.155 49.68 34.425 ;
     RECT  2.16 34.695 49.68 34.965 ;
     RECT  2.16 35.235 49.68 35.505 ;
     RECT  2.16 35.775 49.68 36.045 ;
     RECT  2.16 36.315 49.68 36.585 ;
     RECT  2.16 36.855 49.68 37.125 ;
     RECT  2.16 37.395 49.68 37.665 ;
     RECT  2.16 37.935 49.68 38.205 ;
     RECT  2.16 38.475 49.68 38.745 ;
     RECT  2.16 39.015 49.68 39.285 ;
     RECT  2.16 39.555 49.68 39.825 ;
     RECT  2.16 40.095 49.68 40.365 ;
     RECT  2.16 40.635 49.68 40.905 ;
     RECT  2.16 41.175 49.68 41.445 ;
     RECT  2.16 41.715 49.68 41.985 ;
     RECT  2.16 42.255 49.68 42.525 ;
     RECT  2.16 42.795 49.68 43.065 ;
     RECT  2.16 43.335 49.68 43.605 ;
     RECT  2.16 43.875 49.68 44.145 ;
     RECT  2.16 44.415 49.68 44.685 ;
     RECT  2.16 44.955 49.68 45.225 ;
     RECT  2.16 45.495 49.68 45.765 ;
     RECT  2.16 46.035 49.68 46.305 ;
     RECT  2.16 46.575 49.68 46.845 ;
     RECT  2.16 47.115 49.68 47.385 ;
     RECT  2.16 47.655 49.68 47.925 ;
     RECT  2.16 48.195 49.68 48.465 ;
     RECT  2.16 48.735 49.68 49.005 ;
     RECT  2.16 49.275 49.68 49.545 ;
    LAYER M1 ;
     RECT  2.16 2.151 49.68 49.689 ;
    LAYER M2 ;
     RECT  1.795 2.574 1.939 2.592 ;
     RECT  1.939 2.502 2.16 2.592 ;
     RECT  2.119 5.274 2.16 5.292 ;
     RECT  1.723 47.088 2.16 47.106 ;
     RECT  1.939 48.906 2.16 48.924 ;
     RECT  2.16 2.151 4.567 49.689 ;
     RECT  4.567 2.106 5.747 49.689 ;
     RECT  5.747 2.151 8.383 49.689 ;
     RECT  8.383 2.106 10.139 49.689 ;
     RECT  10.139 2.151 10.903 49.689 ;
     RECT  10.903 2.106 11.831 49.689 ;
     RECT  11.831 2.151 46.147 49.689 ;
     RECT  46.147 2.106 47.983 49.689 ;
     RECT  48.091 50.706 48.335 50.724 ;
     RECT  47.983 2.034 48.551 49.689 ;
     RECT  48.551 2.106 49.559 49.689 ;
     RECT  49.559 2.151 49.68 49.689 ;
     RECT  49.68 3.042 49.739 3.06 ;
     RECT  49.68 49.284 50.207 49.302 ;
    LAYER M3 ;
     RECT  48.06 0.091 48.078 0.427 ;
     RECT  48.06 0.427 48.582 0.523 ;
     RECT  49.32 0.475 49.338 0.523 ;
     RECT  48.06 0.523 49.338 0.571 ;
     RECT  47.16 0.091 47.178 0.667 ;
     RECT  47.916 0.571 49.338 0.667 ;
     RECT  47.16 0.667 49.338 1.675 ;
     RECT  23.544 0.043 23.562 1.723 ;
     RECT  2.736 1.723 12.186 1.771 ;
     RECT  13.068 1.723 25.218 1.771 ;
     RECT  47.124 1.675 49.734 2.101 ;
     RECT  1.8 1.723 1.962 2.143 ;
     RECT  2.736 1.771 25.218 2.143 ;
     RECT  46.152 2.101 46.17 2.143 ;
     RECT  1.8 2.143 25.218 2.191 ;
     RECT  47.088 2.101 49.734 2.251 ;
     RECT  45.615 2.143 46.17 2.335 ;
     RECT  46.944 2.251 49.734 2.335 ;
     RECT  29.415 2.143 29.505 2.413 ;
     RECT  34.815 2.143 34.905 2.413 ;
     RECT  40.215 2.143 40.305 2.413 ;
     RECT  44.496 2.443 44.514 2.489 ;
     RECT  45.612 2.335 49.734 2.497 ;
     RECT  1.8 2.191 25.398 2.597 ;
     RECT  45.288 2.497 49.734 2.641 ;
     RECT  44.568 2.641 49.734 2.831 ;
     RECT  45.144 2.831 49.734 3.065 ;
     RECT  2.34 2.597 25.398 3.181 ;
     RECT  2.34 3.181 25.686 3.343 ;
     RECT  45.144 3.065 49.554 3.443 ;
     RECT  45.144 3.443 49.518 3.569 ;
     RECT  45.615 3.569 45.99 3.605 ;
     RECT  45.615 3.605 45.954 3.641 ;
     RECT  2.34 3.343 25.758 3.721 ;
     RECT  2.34 3.721 26.226 3.979 ;
     RECT  46.764 3.569 49.518 4.109 ;
     RECT  47.016 4.109 49.518 4.415 ;
     RECT  2.124 3.979 26.226 4.541 ;
     RECT  10.296 4.541 26.226 4.781 ;
     RECT  10.44 4.781 26.226 4.919 ;
     RECT  2.124 4.541 9.558 4.955 ;
     RECT  47.232 4.415 49.518 4.991 ;
     RECT  47.376 4.991 49.518 5.027 ;
     RECT  10.44 4.919 11.97 5.189 ;
     RECT  2.124 4.955 9.126 5.297 ;
     RECT  47.448 5.027 49.518 5.341 ;
     RECT  2.34 5.297 9.126 5.459 ;
     RECT  2.34 5.459 3.474 5.495 ;
     RECT  2.415 5.495 3.474 5.837 ;
     RECT  2.415 5.837 3.33 5.873 ;
     RECT  47.448 5.341 49.554 5.909 ;
     RECT  47.016 5.995 47.034 6.035 ;
     RECT  47.988 5.909 49.554 6.035 ;
     RECT  48.096 6.035 49.554 6.107 ;
     RECT  48.636 6.107 49.554 6.143 ;
     RECT  48.636 6.143 49.482 6.269 ;
     RECT  48.636 6.269 49.338 6.305 ;
     RECT  48.636 6.305 49.23 6.413 ;
     RECT  13.215 4.919 26.226 36.391 ;
     RECT  13.215 36.391 26.658 36.461 ;
     RECT  10.62 5.189 11.97 41.755 ;
     RECT  4.248 5.459 9.126 41.953 ;
     RECT  2.415 5.873 3.114 41.989 ;
     RECT  4.14 41.953 9.126 41.989 ;
     RECT  10.62 41.755 12.366 41.989 ;
     RECT  13.215 36.461 26.226 41.989 ;
     RECT  10.62 41.989 26.226 42.053 ;
     RECT  10.656 42.053 26.226 42.179 ;
     RECT  10.836 42.179 26.226 42.287 ;
     RECT  2.415 41.989 9.126 42.331 ;
     RECT  2.376 42.331 9.126 42.509 ;
     RECT  2.415 42.509 9.126 42.601 ;
     RECT  2.415 42.601 9.27 42.755 ;
     RECT  30.78 42.997 30.798 43.097 ;
     RECT  10.836 42.287 26.01 43.105 ;
     RECT  7.815 42.755 9.27 43.141 ;
     RECT  10.26 43.105 26.01 43.141 ;
     RECT  29.415 2.413 29.697 43.681 ;
     RECT  7.815 43.141 26.01 43.807 ;
     RECT  7.815 43.807 26.046 43.843 ;
     RECT  28.8 43.681 29.697 43.879 ;
     RECT  7.815 43.843 26.118 44.041 ;
     RECT  34.815 2.413 35.097 44.041 ;
     RECT  2.415 42.755 7.074 44.113 ;
     RECT  7.815 44.041 26.19 44.113 ;
     RECT  2.415 44.113 26.19 44.149 ;
     RECT  33.768 43.609 33.786 44.311 ;
     RECT  34.815 44.041 35.334 44.311 ;
     RECT  2.34 44.149 26.19 44.666 ;
     RECT  2.34 44.666 26.262 44.689 ;
     RECT  36.576 43.843 36.594 44.725 ;
     RECT  2.34 44.689 26.37 44.731 ;
     RECT  45.615 3.641 45.897 44.761 ;
     RECT  40.215 2.413 40.497 44.923 ;
     RECT  47.628 44.581 47.646 44.995 ;
     RECT  48.636 6.413 48.654 44.995 ;
     RECT  2.34 44.731 26.442 45.005 ;
     RECT  2.415 45.005 26.442 45.031 ;
     RECT  42.408 44.455 42.426 45.121 ;
     RECT  43.164 44.347 43.182 45.121 ;
     RECT  40.215 44.923 40.95 45.157 ;
     RECT  47.628 44.995 48.654 45.157 ;
     RECT  47.628 45.157 49.05 45.301 ;
     RECT  45.615 44.761 46.206 45.427 ;
     RECT  2.415 45.031 26.91 45.463 ;
     RECT  36.432 44.725 36.594 45.463 ;
     RECT  45.324 45.427 46.206 45.499 ;
     RECT  33.768 44.311 35.334 45.571 ;
     RECT  2.415 45.463 26.946 45.661 ;
     RECT  33.084 45.571 35.334 45.805 ;
     RECT  47.628 45.301 49.41 45.841 ;
     RECT  45.324 45.499 46.638 45.931 ;
     RECT  30.78 45.931 30.798 45.967 ;
     RECT  40.215 45.157 41.67 46.003 ;
     RECT  42.408 45.121 43.182 46.003 ;
     RECT  38.952 44.689 38.97 46.039 ;
     RECT  2.415 45.661 27.558 46.075 ;
     RECT  38.952 46.039 39.366 46.111 ;
     RECT  40.215 46.003 43.182 46.111 ;
     RECT  2.415 46.075 27.954 46.201 ;
     RECT  28.728 43.879 29.697 46.201 ;
     RECT  45.216 45.931 46.638 46.219 ;
     RECT  47.628 45.841 49.59 46.219 ;
     RECT  30.744 45.967 30.798 46.237 ;
     RECT  32.544 45.805 35.334 46.237 ;
     RECT  36.432 45.463 37.242 46.237 ;
     RECT  2.415 46.201 29.697 46.273 ;
     RECT  30.708 46.237 30.798 46.273 ;
     RECT  32.544 46.237 37.242 46.309 ;
     RECT  38.952 46.111 43.182 46.381 ;
     RECT  32.508 46.309 37.242 46.471 ;
     RECT  38.088 46.381 43.182 46.471 ;
     RECT  2.415 46.273 30.798 46.543 ;
     RECT  44.46 44.491 44.478 46.741 ;
     RECT  45.216 46.219 49.59 46.741 ;
     RECT  2.34 46.543 30.798 46.747 ;
     RECT  31.644 43.141 31.662 46.747 ;
     RECT  32.508 46.471 43.182 46.777 ;
     RECT  44.46 46.741 49.59 46.777 ;
     RECT  32.508 46.777 43.254 46.813 ;
     RECT  43.992 46.777 49.59 46.813 ;
     RECT  2.34 46.747 31.734 47.011 ;
     RECT  32.508 46.813 49.59 47.011 ;
     RECT  2.34 47.011 49.59 47.083 ;
     RECT  1.728 47.083 49.59 47.309 ;
     RECT  2.34 47.309 49.59 48.901 ;
     RECT  1.944 48.901 49.59 49.279 ;
     RECT  1.944 49.279 50.202 49.421 ;
     RECT  11.808 49.421 30.87 49.469 ;
     RECT  31.608 49.421 33.57 49.469 ;
     RECT  34.308 49.421 50.202 49.469 ;
     RECT  1.944 49.421 10.71 49.517 ;
     RECT  31.68 49.469 33.57 49.517 ;
     RECT  34.38 49.469 37.026 49.517 ;
     RECT  1.944 49.517 7.938 49.541 ;
     RECT  8.964 49.517 10.71 49.541 ;
     RECT  11.88 49.469 30.87 49.541 ;
     RECT  40.032 49.469 50.202 49.541 ;
     RECT  1.944 49.541 7.905 49.565 ;
     RECT  9.792 49.541 10.71 49.565 ;
     RECT  11.88 49.541 26.73 49.565 ;
     RECT  27.504 49.541 30.87 49.565 ;
     RECT  49.248 49.541 50.202 49.565 ;
     RECT  5.652 49.565 7.905 49.577 ;
     RECT  8.964 49.541 8.982 49.577 ;
     RECT  12.492 49.565 19.638 49.577 ;
     RECT  20.376 49.565 26.55 49.577 ;
     RECT  9.792 49.565 9.954 49.613 ;
     RECT  32.004 49.517 33.57 49.613 ;
     RECT  34.38 49.517 36.882 49.613 ;
     RECT  40.032 49.541 48.33 49.613 ;
     RECT  2.415 49.565 3.474 49.697 ;
     RECT  5.688 49.577 7.905 49.697 ;
     RECT  34.38 49.613 36.594 49.697 ;
     RECT  49.464 49.565 50.202 49.709 ;
     RECT  2.736 49.697 3.474 49.805 ;
     RECT  29.376 49.565 30.114 49.805 ;
     RECT  40.032 49.613 44.55 49.805 ;
     RECT  12.492 49.577 14.778 49.853 ;
     RECT  5.688 49.697 7.686 50.141 ;
     RECT  9.936 49.613 9.954 50.141 ;
     RECT  13.968 49.853 14.778 50.141 ;
     RECT  15.732 49.577 19.638 50.141 ;
     RECT  20.376 49.577 26.37 50.141 ;
     RECT  34.38 49.697 34.65 50.141 ;
     RECT  35.496 49.697 36.594 50.141 ;
     RECT  45.324 49.613 48.33 50.141 ;
     RECT  49.5 49.709 50.202 50.141 ;
     RECT  7.02 50.141 7.686 50.189 ;
     RECT  13.968 50.141 13.986 50.189 ;
     RECT  21.78 50.141 26.37 50.189 ;
     RECT  27.504 49.565 28.602 50.189 ;
     RECT  32.184 49.613 33.57 50.189 ;
     RECT  34.38 50.141 34.398 50.189 ;
     RECT  45.756 50.141 45.774 50.189 ;
     RECT  3.456 49.805 3.474 50.717 ;
     RECT  4.608 49.565 4.626 50.717 ;
     RECT  5.688 50.141 6.246 50.717 ;
     RECT  12.492 49.853 13.05 50.717 ;
     RECT  14.76 50.141 14.778 50.717 ;
     RECT  16.164 50.141 16.182 50.717 ;
     RECT  17.064 50.141 19.638 50.717 ;
     RECT  20.736 50.141 20.754 50.717 ;
     RECT  21.78 50.189 22.482 50.717 ;
     RECT  23.292 50.189 24.786 50.717 ;
     RECT  25.524 50.189 25.938 50.717 ;
     RECT  27.828 50.189 28.602 50.717 ;
     RECT  30.096 49.805 30.114 50.717 ;
     RECT  30.852 49.565 30.87 50.717 ;
     RECT  32.796 50.189 33.57 50.717 ;
     RECT  36.576 50.141 36.594 50.717 ;
     RECT  37.764 49.469 37.782 50.717 ;
     RECT  38.52 49.469 38.862 50.717 ;
     RECT  40.032 49.805 40.05 50.717 ;
     RECT  41.004 49.805 44.55 50.717 ;
     RECT  46.836 50.141 46.854 50.717 ;
     RECT  47.628 50.141 48.33 50.717 ;
     RECT  48.096 50.717 48.33 50.729 ;
     RECT  17.064 50.717 17.082 50.765 ;
     RECT  41.004 50.717 41.022 50.765 ;
     RECT  48.312 50.729 48.33 50.765 ;
     RECT  50.184 50.141 50.202 50.765 ;
    LAYER M4 ;
     RECT  1.237 4.56 1.429 4.584 ;
     RECT  1.045 1.776 1.745 1.8 ;
     RECT  1.429 4.56 2.069 4.68 ;
     RECT  2.069 3.984 2.329 4.68 ;
     RECT  1.189 45.504 2.329 45.528 ;
     RECT  1.525 47.28 2.329 47.304 ;
     RECT  2.329 46.56 2.365 47.304 ;
     RECT  2.365 46.56 2.401 48.168 ;
     RECT  1.745 1.728 2.408 1.8 ;
     RECT  2.329 3.696 2.408 4.68 ;
     RECT  2.365 42.48 2.408 42.504 ;
     RECT  2.329 44.976 2.408 45.528 ;
     RECT  2.401 46.56 2.408 48.456 ;
     RECT  1.889 49.536 2.408 49.56 ;
     RECT  2.408 1.728 2.677 49.692 ;
     RECT  2.677 1.728 2.704 49.8 ;
     RECT  2.704 49.536 2.765 49.8 ;
     RECT  2.704 42 3.443 43.512 ;
     RECT  3.443 42 3.484 42.024 ;
     RECT  2.704 3.696 3.521 3.72 ;
     RECT  3.445 50.688 3.529 50.712 ;
     RECT  2.704 1.728 3.539 2.28 ;
     RECT  2.704 44.976 3.875 46.632 ;
     RECT  3.875 45.168 3.953 46.632 ;
     RECT  3.953 45.552 4.021 46.632 ;
     RECT  3.443 43.056 4.213 43.512 ;
     RECT  2.704 47.856 4.268 48.456 ;
     RECT  4.213 43.056 4.3 44.088 ;
     RECT  4.268 47.76 4.345 48.456 ;
     RECT  4.345 47.76 4.355 48.504 ;
     RECT  4.021 45.552 4.501 46.776 ;
     RECT  3.985 3.888 4.525 3.912 ;
     RECT  4.3 43.056 4.547 43.512 ;
     RECT  3.539 1.728 4.565 1.944 ;
     RECT  4.501 45.552 4.565 46.872 ;
     RECT  4.525 3.408 4.601 3.912 ;
     RECT  4.601 3.408 4.633 3.432 ;
     RECT  2.765 49.536 5.033 49.56 ;
     RECT  4.565 45.552 5.069 45.576 ;
     RECT  4.565 46.752 5.069 46.872 ;
     RECT  5.18 44.976 5.267 45 ;
     RECT  4.633 2.784 5.285 3.432 ;
     RECT  4.355 48.432 5.461 48.504 ;
     RECT  4.547 43.488 5.537 43.512 ;
     RECT  2.704 5.088 5.605 5.112 ;
     RECT  5.605 4.56 5.717 5.112 ;
     RECT  4.597 50.688 5.741 50.712 ;
     RECT  5.069 46.8 5.821 46.872 ;
     RECT  5.461 48.432 5.933 49.032 ;
     RECT  5.821 46.8 5.969 47.112 ;
     RECT  5.717 4.56 6.005 4.92 ;
     RECT  5.933 48.432 6.257 48.792 ;
     RECT  5.741 50.112 6.257 50.712 ;
     RECT  4.565 1.728 6.757 1.8 ;
     RECT  5.969 46.8 6.793 46.872 ;
     RECT  6.793 46.752 6.833 46.872 ;
     RECT  6.257 48.768 7.237 48.792 ;
     RECT  6.257 50.112 7.237 50.184 ;
     RECT  6.833 46.752 7.261 46.776 ;
     RECT  6.005 4.896 7.693 4.92 ;
     RECT  7.237 48.768 7.708 50.184 ;
     RECT  7.708 48.768 7.765 49.8 ;
     RECT  6.757 1.728 7.808 2.28 ;
     RECT  5.285 3.408 7.808 3.432 ;
     RECT  7.693 4.752 7.808 4.92 ;
     RECT  6.793 44.208 7.808 44.232 ;
     RECT  7.261 46.56 7.808 46.776 ;
     RECT  7.765 47.904 7.808 49.8 ;
     RECT  7.808 1.728 8.104 49.8 ;
     RECT  8.104 49.344 8.243 49.8 ;
     RECT  8.243 49.344 8.561 49.512 ;
     RECT  8.104 46.512 9.349 46.776 ;
     RECT  8.104 1.728 9.493 1.848 ;
     RECT  8.104 4.752 9.493 4.776 ;
     RECT  8.104 47.904 9.565 47.976 ;
     RECT  9.493 1.728 9.605 1.896 ;
     RECT  8.561 49.488 9.677 49.512 ;
     RECT  9.349 46.368 9.749 46.776 ;
     RECT  9.925 49.536 10.009 50.136 ;
     RECT  9.493 4.512 10.325 4.776 ;
     RECT  10.009 49.536 10.765 49.56 ;
     RECT  10.325 4.512 10.861 4.68 ;
     RECT  10.861 4.224 10.969 4.68 ;
     RECT  10.861 42.672 10.973 42.696 ;
     RECT  10.969 3.888 11.041 4.68 ;
     RECT  9.565 47.904 11.077 48.456 ;
     RECT  11.041 3.408 11.221 4.68 ;
     RECT  9.605 1.728 11.365 1.8 ;
     RECT  9.749 46.512 11.473 46.776 ;
     RECT  11.077 47.904 11.477 49.416 ;
     RECT  11.477 48.432 11.797 49.416 ;
     RECT  11.797 48.432 11.801 49.56 ;
     RECT  11.365 1.728 11.861 1.848 ;
     RECT  11.801 49.536 11.909 49.56 ;
     RECT  11.473 46.512 12.233 46.92 ;
     RECT  12.181 50.688 12.565 50.712 ;
     RECT  11.801 48.432 12.661 48.456 ;
     RECT  12.661 48.192 12.805 48.456 ;
     RECT  12.565 50.64 13.061 50.712 ;
     RECT  11.861 1.728 13.165 1.896 ;
     RECT  11.221 3.12 13.165 4.68 ;
     RECT  13.165 1.728 13.208 4.68 ;
     RECT  12.233 46.752 13.208 46.92 ;
     RECT  12.805 48.192 13.208 48.792 ;
     RECT  13.208 1.728 13.504 50.184 ;
     RECT  13.504 1.728 13.565 1.848 ;
     RECT  13.504 46.608 14.033 48.792 ;
     RECT  14.033 46.608 14.243 48.216 ;
     RECT  13.504 50.112 14.249 50.184 ;
     RECT  14.243 46.608 14.321 47.688 ;
     RECT  13.504 3.024 14.605 4.68 ;
     RECT  14.485 50.688 14.789 50.712 ;
     RECT  14.605 3.024 14.929 5.208 ;
     RECT  14.869 49.392 15.149 49.416 ;
     RECT  13.504 41.952 15.217 41.976 ;
     RECT  14.569 43.344 15.325 43.368 ;
     RECT  15.253 49.536 15.401 49.56 ;
     RECT  15.325 43.344 15.505 43.848 ;
     RECT  14.677 45.6 15.505 45.624 ;
     RECT  15.505 43.344 15.869 45.624 ;
     RECT  14.321 46.608 15.905 46.776 ;
     RECT  15.637 50.112 16.021 50.136 ;
     RECT  15.217 41.616 16.049 41.976 ;
     RECT  15.905 46.752 16.225 46.776 ;
     RECT  14.929 2.832 16.301 5.208 ;
     RECT  16.117 41.04 16.337 41.064 ;
     RECT  16.297 42.288 16.441 42.36 ;
     RECT  15.869 43.344 16.441 44.952 ;
     RECT  16.301 3.6 16.445 5.208 ;
     RECT  16.021 50.112 16.489 50.712 ;
     RECT  16.445 3.6 16.589 4.152 ;
     RECT  16.589 3.936 16.769 4.152 ;
     RECT  15.685 48.24 16.877 48.264 ;
     RECT  16.789 49.488 16.985 49.512 ;
     RECT  16.225 46.752 17.017 46.824 ;
     RECT  17.017 46.752 17.125 46.872 ;
     RECT  17.053 50.736 17.171 50.76 ;
     RECT  16.769 3.936 17.345 3.96 ;
     RECT  13.565 1.728 17.372 1.8 ;
     RECT  17.125 46.368 17.417 46.872 ;
     RECT  17.372 1.728 17.459 2.28 ;
     RECT  17.269 48.384 17.485 48.408 ;
     RECT  17.417 46.752 17.593 46.872 ;
     RECT  16.441 42.288 17.881 44.952 ;
     RECT  17.485 48.384 18.061 48.456 ;
     RECT  17.593 46.752 18.277 47.352 ;
     RECT  18.061 48.384 18.277 48.792 ;
     RECT  17.459 1.728 18.565 1.8 ;
     RECT  18.565 1.728 18.608 2.04 ;
     RECT  16.445 5.184 18.608 5.208 ;
     RECT  17.881 41.472 18.608 44.952 ;
     RECT  18.277 46.752 18.608 48.792 ;
     RECT  18.608 1.728 18.712 49.692 ;
     RECT  18.712 1.728 18.904 49.422 ;
     RECT  18.904 3.12 18.965 3.144 ;
     RECT  18.904 41.904 18.965 49.422 ;
     RECT  19.781 49.536 19.865 49.56 ;
     RECT  18.904 1.728 20.108 1.8 ;
     RECT  20.108 1.728 20.195 2.28 ;
     RECT  17.509 50.688 20.197 50.712 ;
     RECT  20.195 1.728 20.477 1.848 ;
     RECT  18.965 41.904 20.533 48.168 ;
     RECT  20.533 41.904 20.621 49.08 ;
     RECT  20.621 41.904 20.956 48.408 ;
     RECT  20.956 44.832 21.017 48.408 ;
     RECT  21.017 44.88 21.089 48.408 ;
     RECT  20.956 41.904 21.193 43.752 ;
     RECT  20.477 1.728 21.473 1.752 ;
     RECT  20.197 50.112 21.485 50.712 ;
     RECT  21.193 41.856 21.557 43.752 ;
     RECT  21.089 46.56 21.697 48.408 ;
     RECT  21.557 43.296 21.881 43.752 ;
     RECT  21.557 41.856 21.985 41.928 ;
     RECT  21.697 46.56 22.069 48.456 ;
     RECT  21.881 43.392 22.129 43.752 ;
     RECT  21.089 44.88 22.129 45.576 ;
     RECT  21.985 41.04 22.133 41.928 ;
     RECT  22.133 41.04 22.241 41.88 ;
     RECT  22.069 46.56 22.241 49.416 ;
     RECT  22.309 4.176 22.381 4.2 ;
     RECT  21.485 50.688 22.837 50.712 ;
     RECT  22.129 43.392 22.885 45.576 ;
     RECT  22.241 46.56 22.885 48.936 ;
     RECT  22.837 50.16 22.925 50.712 ;
     RECT  22.885 43.392 22.961 48.936 ;
     RECT  22.961 43.392 22.997 48.456 ;
     RECT  22.997 43.392 23.137 48.264 ;
     RECT  22.381 3.312 23.324 4.2 ;
     RECT  18.904 5.184 23.324 5.208 ;
     RECT  23.137 43.296 23.353 48.264 ;
     RECT  22.705 17.904 23.497 17.928 ;
     RECT  21.473 1.728 23.749 1.8 ;
     RECT  23.749 1.728 23.929 1.848 ;
     RECT  23.929 1.728 24.008 2.04 ;
     RECT  23.324 3.312 24.008 5.208 ;
     RECT  23.497 17.664 24.008 17.928 ;
     RECT  22.241 41.856 24.008 41.88 ;
     RECT  23.353 42.96 24.008 48.264 ;
     RECT  24.008 1.728 24.112 49.692 ;
     RECT  24.112 1.728 24.304 49.422 ;
     RECT  24.304 1.728 24.323 2.04 ;
     RECT  24.323 1.728 24.509 1.848 ;
     RECT  24.304 43.728 24.833 49.032 ;
     RECT  24.509 1.728 24.905 1.8 ;
     RECT  22.925 50.688 25.141 50.712 ;
     RECT  24.905 1.728 25.229 1.752 ;
     RECT  25.141 50.16 25.301 50.712 ;
     RECT  24.304 25.776 25.436 25.8 ;
     RECT  24.304 17.904 25.523 17.928 ;
     RECT  25.436 25.776 25.523 26.136 ;
     RECT  25.469 35.904 25.553 35.928 ;
     RECT  24.833 43.872 25.985 49.032 ;
     RECT  25.301 50.688 25.993 50.712 ;
     RECT  25.985 44.112 26.201 49.032 ;
     RECT  26.293 50.16 26.381 50.184 ;
     RECT  26.201 44.352 26.657 49.032 ;
     RECT  26.629 36.432 26.713 36.456 ;
     RECT  26.657 44.352 26.741 49.56 ;
     RECT  26.741 44.352 27.148 49.128 ;
     RECT  27.397 50.16 27.533 50.184 ;
     RECT  27.773 50.688 28.613 50.712 ;
     RECT  27.148 44.352 28.933 48.744 ;
     RECT  28.933 44.352 29.317 49.56 ;
     RECT  24.304 4.128 29.408 4.152 ;
     RECT  25.523 25.776 29.408 25.8 ;
     RECT  29.317 44.352 29.408 49.8 ;
     RECT  29.408 2.148 29.512 49.8 ;
     RECT  29.512 2.418 29.704 49.8 ;
     RECT  29.704 49.536 29.801 49.8 ;
     RECT  29.801 49.536 30.593 49.56 ;
     RECT  29.704 45.408 30.913 48.168 ;
     RECT  30.085 50.688 30.925 50.712 ;
     RECT  30.913 45.408 31.621 49.416 ;
     RECT  31.621 45.408 32.005 49.512 ;
     RECT  32.005 45.408 32.213 50.184 ;
     RECT  32.213 45.408 32.465 49.56 ;
     RECT  32.725 50.688 33.581 50.712 ;
     RECT  32.465 45.408 33.865 48.84 ;
     RECT  33.865 45.408 33.877 49.032 ;
     RECT  33.877 45.408 34.261 49.416 ;
     RECT  34.261 45.408 34.409 50.184 ;
     RECT  29.704 4.128 34.808 4.152 ;
     RECT  29.704 25.776 34.808 25.8 ;
     RECT  29.704 44.352 34.808 44.376 ;
     RECT  34.409 45.408 34.808 50.136 ;
     RECT  34.808 2.148 34.912 50.136 ;
     RECT  34.912 2.418 35.104 50.136 ;
     RECT  35.104 45.408 35.921 50.136 ;
     RECT  35.921 49.44 36.029 50.136 ;
     RECT  36.029 49.488 36.245 50.136 ;
     RECT  35.921 45.408 36.569 48.456 ;
     RECT  36.565 50.688 36.649 50.712 ;
     RECT  36.245 49.488 37.037 49.512 ;
     RECT  37.333 49.2 37.577 49.224 ;
     RECT  38.053 49.392 38.189 49.416 ;
     RECT  36.569 45.408 38.761 48.12 ;
     RECT  37.669 50.688 38.873 50.712 ;
     RECT  38.761 45.408 39.589 48.216 ;
     RECT  39.205 49.44 39.589 49.464 ;
     RECT  35.104 4.128 40.208 4.152 ;
     RECT  35.104 25.776 40.208 25.8 ;
     RECT  35.104 44.352 40.208 44.376 ;
     RECT  39.589 45.408 40.208 49.464 ;
     RECT  40.208 2.148 40.312 49.692 ;
     RECT  40.312 2.418 40.345 49.692 ;
     RECT  39.973 50.688 40.345 50.712 ;
     RECT  40.345 2.418 40.429 50.712 ;
     RECT  40.429 2.418 40.504 49.422 ;
     RECT  40.504 45.408 41.033 49.416 ;
     RECT  40.993 50.736 41.171 50.76 ;
     RECT  41.033 45.408 41.645 48.504 ;
     RECT  41.645 45.408 42.613 48.312 ;
     RECT  42.613 45.408 42.661 49.032 ;
     RECT  42.661 45.408 42.725 49.416 ;
     RECT  42.725 48.288 42.761 49.416 ;
     RECT  42.725 45.408 42.797 47.304 ;
     RECT  40.504 44.352 43.193 44.376 ;
     RECT  42.797 45.504 43.837 47.256 ;
     RECT  42.761 48.288 43.837 49.032 ;
     RECT  43.837 45.504 44.057 49.032 ;
     RECT  44.057 45.504 44.129 47.208 ;
     RECT  44.485 2.448 44.557 2.472 ;
     RECT  41.489 50.688 44.605 50.712 ;
     RECT  44.057 48.384 44.917 49.032 ;
     RECT  44.557 2.448 45.089 2.808 ;
     RECT  40.504 4.128 45.089 4.152 ;
     RECT  44.917 48.384 45.269 49.512 ;
     RECT  45.089 2.448 45.608 4.152 ;
     RECT  40.504 25.776 45.608 25.8 ;
     RECT  44.129 45.504 45.608 47.16 ;
     RECT  45.269 48.384 45.608 50.136 ;
     RECT  45.608 2.148 45.685 50.136 ;
     RECT  45.685 2.148 45.712 50.184 ;
     RECT  45.712 2.418 45.785 50.184 ;
     RECT  45.785 2.418 45.904 50.136 ;
     RECT  45.904 45.504 46.649 48.216 ;
     RECT  45.904 50.112 46.825 50.136 ;
     RECT  45.904 2.784 46.892 4.152 ;
     RECT  46.892 2.256 46.979 4.152 ;
     RECT  46.825 50.112 47.077 50.712 ;
     RECT  23.533 0.048 47.149 0.072 ;
     RECT  47.077 49.344 47.305 50.712 ;
     RECT  47.149 0.048 47.365 0.12 ;
     RECT  46.979 2.832 47.369 4.152 ;
     RECT  46.649 46.224 47.477 48.216 ;
     RECT  47.005 6 47.509 6.024 ;
     RECT  47.113 1.68 47.699 1.8 ;
     RECT  47.365 0.048 47.941 0.696 ;
     RECT  47.369 2.832 48.013 3.96 ;
     RECT  47.509 5.808 48.121 6.024 ;
     RECT  47.477 47.136 48.157 48.216 ;
     RECT  47.305 49.344 48.157 49.368 ;
     RECT  48.121 5.184 48.265 6.024 ;
     RECT  48.157 47.136 48.268 49.368 ;
     RECT  48.181 45.552 48.269 45.576 ;
     RECT  48.268 48.192 48.284 49.368 ;
     RECT  47.305 50.688 48.284 50.712 ;
     RECT  48.284 48.192 48.301 50.712 ;
     RECT  48.013 2.256 48.305 3.96 ;
     RECT  48.305 2.256 48.371 3.432 ;
     RECT  48.301 48.192 48.371 50.76 ;
     RECT  48.371 48.192 48.521 49.56 ;
     RECT  48.445 46.752 48.557 46.776 ;
     RECT  48.265 5.088 48.629 6.024 ;
     RECT  48.371 50.736 48.755 50.76 ;
     RECT  45.904 25.776 48.899 25.8 ;
     RECT  48.371 2.592 49.025 3.432 ;
     RECT  48.629 5.184 49.061 5.784 ;
     RECT  49.061 5.76 49.097 5.784 ;
     RECT  47.941 0.048 49.139 1.128 ;
     RECT  48.913 45.408 49.241 45.432 ;
     RECT  49.025 2.832 49.277 3.432 ;
     RECT  49.277 2.832 49.379 2.904 ;
     RECT  48.521 49.344 49.445 49.56 ;
     RECT  49.445 49.344 49.529 50.136 ;
     RECT  49.529 49.344 49.561 49.704 ;
     RECT  49.379 2.832 49.571 2.856 ;
     RECT  49.139 0.096 49.676 1.128 ;
     RECT  49.676 0.096 49.763 1.704 ;
     RECT  49.561 49.008 49.907 49.704 ;
     RECT  49.763 0.096 50.243 1.128 ;
     RECT  49.907 49.68 50.291 49.704 ;
     RECT  50.243 0.096 50.435 0.696 ;
     RECT  50.435 0.432 50.627 0.696 ;
     RECT  50.173 50.736 50.675 50.76 ;
     RECT  50.627 0.432 50.771 0.456 ;
    LAYER M5 ;
     RECT  47.328 0.016 50.76 0.467 ;
     RECT  47.328 0.467 50.616 0.707 ;
     RECT  47.328 0.707 50.232 1.139 ;
     RECT  47.328 1.139 49.752 1.715 ;
     RECT  1.056 0.016 25.176 1.763 ;
     RECT  1.056 1.763 9.528 1.811 ;
     RECT  10.512 1.763 20.328 1.811 ;
     RECT  21.504 1.763 22.248 1.811 ;
     RECT  23.232 1.763 24.792 1.811 ;
     RECT  47.328 1.715 49.56 1.811 ;
     RECT  1.248 1.811 4.536 1.859 ;
     RECT  6.912 1.811 9.528 1.859 ;
     RECT  11.376 1.811 13.512 1.859 ;
     RECT  20.16 1.811 20.328 1.859 ;
     RECT  23.76 1.811 24.456 1.859 ;
     RECT  9.504 1.859 9.528 1.907 ;
     RECT  11.904 1.859 13.512 1.907 ;
     RECT  4.512 1.859 4.536 1.955 ;
     RECT  29.4 2.137 29.52 2.151 ;
     RECT  34.8 2.137 34.92 2.151 ;
     RECT  40.2 2.137 40.32 2.151 ;
     RECT  45.6 2.137 45.72 2.151 ;
     RECT  1.248 1.859 3.528 2.291 ;
     RECT  6.912 1.859 8.112 2.291 ;
     RECT  17.424 1.811 17.448 2.291 ;
     RECT  20.16 1.859 20.184 2.291 ;
     RECT  48.336 1.811 49.56 2.291 ;
     RECT  45.6 2.151 45.912 2.437 ;
     RECT  48.864 2.291 49.56 2.867 ;
     RECT  48.864 2.867 49.368 2.915 ;
     RECT  46.944 2.245 46.968 3.251 ;
     RECT  45.12 2.437 45.912 3.443 ;
     RECT  48.864 2.915 49.224 3.443 ;
     RECT  24 1.859 24.312 4.117 ;
     RECT  1.248 2.291 2.712 4.595 ;
     RECT  1.44 4.595 2.712 4.691 ;
     RECT  23.376 4.117 24.312 5.219 ;
     RECT  23.52 5.219 24.312 17.699 ;
     RECT  48.864 3.443 48.888 25.811 ;
     RECT  25.488 17.893 25.512 35.939 ;
     RECT  24 17.699 24.312 41.845 ;
     RECT  2.4 4.691 2.712 41.989 ;
     RECT  2.4 41.989 3.432 43.477 ;
     RECT  4.512 43.045 4.536 43.477 ;
     RECT  23.616 41.845 24.312 43.861 ;
     RECT  22.656 43.861 24.312 44.147 ;
     RECT  20.88 43.765 20.904 44.723 ;
     RECT  2.4 43.477 5.256 45.011 ;
     RECT  45.6 3.443 45.912 46.453 ;
     RECT  13.2 1.907 13.512 46.597 ;
     RECT  2.4 45.011 4.536 46.643 ;
     RECT  23.616 44.147 24.312 46.787 ;
     RECT  34.8 2.151 35.112 46.789 ;
     RECT  26.64 36.421 26.664 46.885 ;
     RECT  26.208 46.885 26.664 46.931 ;
     RECT  1.2 45.493 1.224 47.269 ;
     RECT  2.4 46.643 2.712 47.269 ;
     RECT  40.2 2.151 40.512 47.269 ;
     RECT  48.192 45.541 48.216 47.459 ;
     RECT  28.032 47.461 28.056 47.651 ;
     RECT  9.648 46.645 9.672 47.939 ;
     RECT  33.264 47.077 33.288 47.939 ;
     RECT  45.6 46.453 46.152 47.939 ;
     RECT  26.208 46.931 26.232 48.131 ;
     RECT  3.84 46.643 4.536 48.179 ;
     RECT  34.8 46.789 35.208 48.179 ;
     RECT  13.2 46.597 14.232 48.227 ;
     RECT  42.144 46.741 42.168 48.323 ;
     RECT  4.32 48.179 4.536 48.467 ;
     RECT  5.904 46.789 5.928 48.467 ;
     RECT  4.512 48.467 4.536 48.515 ;
     RECT  24 46.787 24.312 48.901 ;
     RECT  40.2 47.269 40.776 48.997 ;
     RECT  24 48.901 25.08 49.043 ;
     RECT  43.344 48.277 43.368 49.043 ;
     RECT  20.544 47.221 20.568 49.091 ;
     RECT  7.8 2.291 8.112 49.333 ;
     RECT  7.8 49.333 8.424 49.381 ;
     RECT  34.8 48.179 35.112 49.381 ;
     RECT  37.344 49.189 37.368 49.381 ;
     RECT  33.888 49.381 35.112 49.429 ;
     RECT  39.6 48.997 40.776 49.429 ;
     RECT  7.248 49.381 8.424 49.477 ;
     RECT  31.248 49.381 31.272 49.477 ;
     RECT  37.344 49.381 38.088 49.477 ;
     RECT  45.6 47.939 45.912 49.477 ;
     RECT  1.2 47.269 2.712 49.525 ;
     RECT  7.248 49.477 9.576 49.525 ;
     RECT  11.088 49.381 11.496 49.525 ;
     RECT  14.88 49.381 14.904 49.525 ;
     RECT  18.6 1.811 18.912 49.525 ;
     RECT  27.072 49.093 27.096 49.525 ;
     RECT  29.4 2.151 29.712 49.525 ;
     RECT  31.248 49.477 31.656 49.525 ;
     RECT  49.872 48.997 49.896 49.525 ;
     RECT  49.104 49.525 49.896 49.669 ;
     RECT  18.6 49.525 19.848 49.689 ;
     RECT  24 49.043 24.312 49.689 ;
     RECT  18.6 49.689 18.72 49.703 ;
     RECT  24 49.689 24.12 49.703 ;
     RECT  1.2 49.525 5.016 50.101 ;
     RECT  7.248 49.525 11.832 50.101 ;
     RECT  13.2 48.227 13.512 50.101 ;
     RECT  14.88 49.525 15.288 50.101 ;
     RECT  16.8 49.477 16.824 50.101 ;
     RECT  19.824 49.689 19.848 50.101 ;
     RECT  22.08 49.381 22.104 50.101 ;
     RECT  33.888 49.429 35.832 50.101 ;
     RECT  36.96 49.477 38.088 50.101 ;
     RECT  44.928 49.477 45.912 50.101 ;
     RECT  19.824 50.101 22.104 50.149 ;
     RECT  26.688 49.525 27.096 50.149 ;
     RECT  49.104 49.669 50.28 50.149 ;
     RECT  1.2 50.101 11.832 50.629 ;
     RECT  13.2 50.101 16.824 50.629 ;
     RECT  1.2 50.629 16.824 50.677 ;
     RECT  19.824 50.149 22.872 50.677 ;
     RECT  25.152 50.149 25.176 50.677 ;
     RECT  26.304 50.149 27.432 50.677 ;
     RECT  28.944 49.525 32.424 50.677 ;
     RECT  33.888 50.101 38.088 50.677 ;
     RECT  39.216 49.429 40.776 50.677 ;
     RECT  42.672 49.381 42.696 50.677 ;
     RECT  44.928 50.101 47.256 50.677 ;
     RECT  48.336 50.149 50.28 50.677 ;
     RECT  1.2 50.677 50.28 50.725 ;
     RECT  1.2 50.725 50.664 51.792 ;
  END
END ot_hbm_pc_refresh_cfg
END LIBRARY
